VERSION 5.7 ;
  NOWIREEXTENSIONATPIN ON ;
  DIVIDERCHAR "/" ;
  BUSBITCHARS "[]" ;
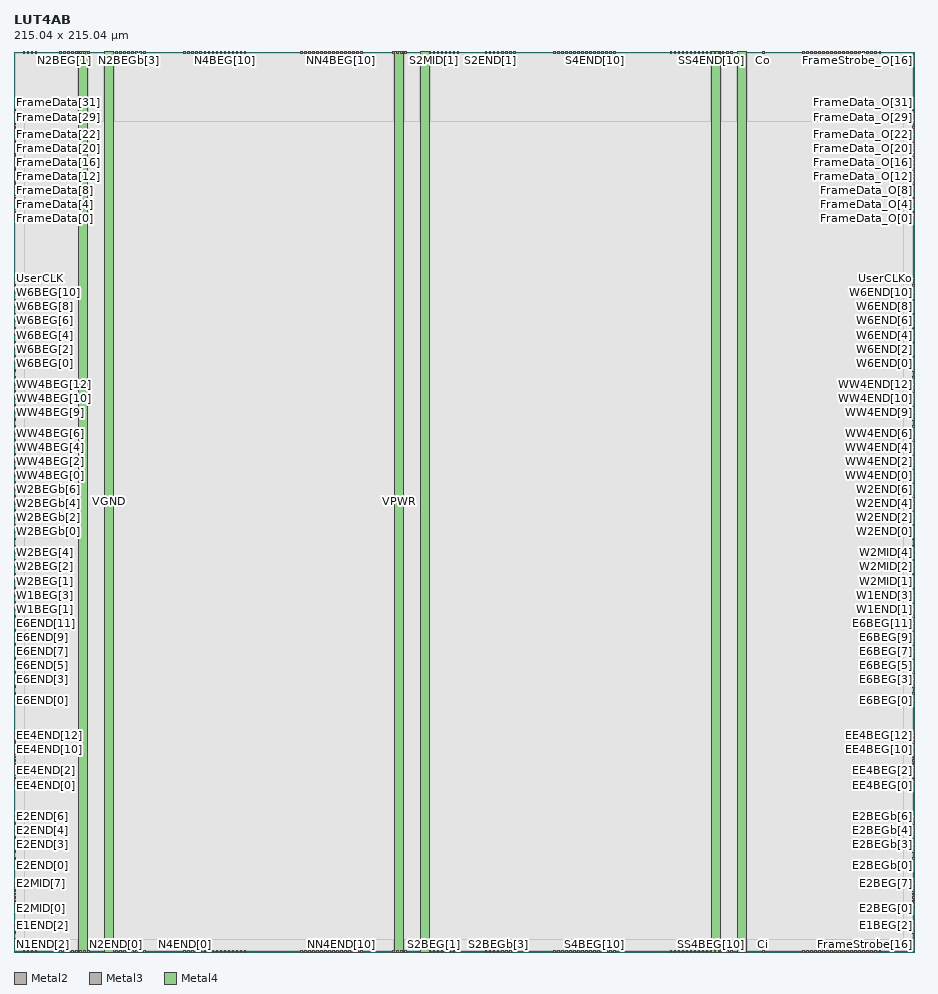
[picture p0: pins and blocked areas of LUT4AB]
MACRO LUT4AB
  CLASS BLOCK ;
  FOREIGN LUT4AB ;
  ORIGIN 0.000 0.000 ;
  SIZE 215.040 BY 215.040 ;
  PIN Ci
    DIRECTION INPUT ;
    USE SIGNAL ;
    ANTENNAGATEAREA 0.587600 ;
    PORT
      LAYER Metal2 ;
        RECT 178.840 0.000 179.240 0.400 ;
    END
  END Ci
  PIN Co
    DIRECTION OUTPUT ;
    USE SIGNAL ;
    ANTENNADIFFAREA 2.692600 ;
    PORT
      LAYER Metal2 ;
        RECT 178.840 214.640 179.240 215.040 ;
    END
  END Co
  PIN E1BEG[0]
    DIRECTION OUTPUT ;
    USE SIGNAL ;
    ANTENNADIFFAREA 2.724000 ;
    PORT
      LAYER Metal3 ;
        RECT 214.640 1.060 215.040 1.460 ;
    END
  END E1BEG[0]
  PIN E1BEG[1]
    DIRECTION OUTPUT ;
    USE SIGNAL ;
    ANTENNADIFFAREA 2.724000 ;
    PORT
      LAYER Metal3 ;
        RECT 214.640 2.740 215.040 3.140 ;
    END
  END E1BEG[1]
  PIN E1BEG[2]
    DIRECTION OUTPUT ;
    USE SIGNAL ;
    ANTENNADIFFAREA 2.724000 ;
    PORT
      LAYER Metal3 ;
        RECT 214.640 4.420 215.040 4.820 ;
    END
  END E1BEG[2]
  PIN E1BEG[3]
    DIRECTION OUTPUT ;
    USE SIGNAL ;
    ANTENNADIFFAREA 2.724000 ;
    PORT
      LAYER Metal3 ;
        RECT 214.640 6.100 215.040 6.500 ;
    END
  END E1BEG[3]
  PIN E1END[0]
    DIRECTION INPUT ;
    USE SIGNAL ;
    ANTENNAGATEAREA 1.917500 ;
    PORT
      LAYER Metal3 ;
        RECT 0.000 1.060 0.400 1.460 ;
    END
  END E1END[0]
  PIN E1END[1]
    DIRECTION INPUT ;
    USE SIGNAL ;
    ANTENNAGATEAREA 1.847300 ;
    PORT
      LAYER Metal3 ;
        RECT 0.000 2.740 0.400 3.140 ;
    END
  END E1END[1]
  PIN E1END[2]
    DIRECTION INPUT ;
    USE SIGNAL ;
    ANTENNAGATEAREA 2.448700 ;
    PORT
      LAYER Metal3 ;
        RECT 0.000 4.420 0.400 4.820 ;
    END
  END E1END[2]
  PIN E1END[3]
    DIRECTION INPUT ;
    USE SIGNAL ;
    ANTENNAGATEAREA 2.433100 ;
    PORT
      LAYER Metal3 ;
        RECT 0.000 6.100 0.400 6.500 ;
    END
  END E1END[3]
  PIN E2BEG[0]
    DIRECTION OUTPUT ;
    USE SIGNAL ;
    ANTENNADIFFAREA 2.724000 ;
    PORT
      LAYER Metal3 ;
        RECT 214.640 10.300 215.040 10.700 ;
    END
  END E2BEG[0]
  PIN E2BEG[1]
    DIRECTION OUTPUT ;
    USE SIGNAL ;
    ANTENNADIFFAREA 2.724000 ;
    PORT
      LAYER Metal3 ;
        RECT 214.640 11.140 215.040 11.540 ;
    END
  END E2BEG[1]
  PIN E2BEG[2]
    DIRECTION OUTPUT ;
    USE SIGNAL ;
    ANTENNADIFFAREA 2.724000 ;
    PORT
      LAYER Metal3 ;
        RECT 214.640 11.980 215.040 12.380 ;
    END
  END E2BEG[2]
  PIN E2BEG[3]
    DIRECTION OUTPUT ;
    USE SIGNAL ;
    ANTENNADIFFAREA 2.724000 ;
    PORT
      LAYER Metal3 ;
        RECT 214.640 12.820 215.040 13.220 ;
    END
  END E2BEG[3]
  PIN E2BEG[4]
    DIRECTION OUTPUT ;
    USE SIGNAL ;
    ANTENNADIFFAREA 2.724000 ;
    PORT
      LAYER Metal3 ;
        RECT 214.640 13.660 215.040 14.060 ;
    END
  END E2BEG[4]
  PIN E2BEG[5]
    DIRECTION OUTPUT ;
    USE SIGNAL ;
    ANTENNADIFFAREA 2.724000 ;
    PORT
      LAYER Metal3 ;
        RECT 214.640 14.500 215.040 14.900 ;
    END
  END E2BEG[5]
  PIN E2BEG[6]
    DIRECTION OUTPUT ;
    USE SIGNAL ;
    ANTENNADIFFAREA 2.724000 ;
    PORT
      LAYER Metal3 ;
        RECT 214.640 15.340 215.040 15.740 ;
    END
  END E2BEG[6]
  PIN E2BEG[7]
    DIRECTION OUTPUT ;
    USE SIGNAL ;
    ANTENNADIFFAREA 2.724000 ;
    PORT
      LAYER Metal3 ;
        RECT 214.640 16.180 215.040 16.580 ;
    END
  END E2BEG[7]
  PIN E2BEGb[0]
    DIRECTION OUTPUT ;
    USE SIGNAL ;
    ANTENNADIFFAREA 2.724000 ;
    PORT
      LAYER Metal3 ;
        RECT 214.640 20.380 215.040 20.780 ;
    END
  END E2BEGb[0]
  PIN E2BEGb[1]
    DIRECTION OUTPUT ;
    USE SIGNAL ;
    ANTENNADIFFAREA 2.724000 ;
    PORT
      LAYER Metal3 ;
        RECT 214.640 22.060 215.040 22.460 ;
    END
  END E2BEGb[1]
  PIN E2BEGb[2]
    DIRECTION OUTPUT ;
    USE SIGNAL ;
    ANTENNADIFFAREA 2.724000 ;
    PORT
      LAYER Metal3 ;
        RECT 214.640 23.740 215.040 24.140 ;
    END
  END E2BEGb[2]
  PIN E2BEGb[3]
    DIRECTION OUTPUT ;
    USE SIGNAL ;
    ANTENNADIFFAREA 2.724000 ;
    PORT
      LAYER Metal3 ;
        RECT 214.640 25.420 215.040 25.820 ;
    END
  END E2BEGb[3]
  PIN E2BEGb[4]
    DIRECTION OUTPUT ;
    USE SIGNAL ;
    ANTENNADIFFAREA 2.724000 ;
    PORT
      LAYER Metal3 ;
        RECT 214.640 27.100 215.040 27.500 ;
    END
  END E2BEGb[4]
  PIN E2BEGb[5]
    DIRECTION OUTPUT ;
    USE SIGNAL ;
    ANTENNADIFFAREA 2.724000 ;
    PORT
      LAYER Metal3 ;
        RECT 214.640 28.780 215.040 29.180 ;
    END
  END E2BEGb[5]
  PIN E2BEGb[6]
    DIRECTION OUTPUT ;
    USE SIGNAL ;
    ANTENNADIFFAREA 2.724000 ;
    PORT
      LAYER Metal3 ;
        RECT 214.640 30.460 215.040 30.860 ;
    END
  END E2BEGb[6]
  PIN E2BEGb[7]
    DIRECTION OUTPUT ;
    USE SIGNAL ;
    ANTENNADIFFAREA 2.724000 ;
    PORT
      LAYER Metal3 ;
        RECT 214.640 32.140 215.040 32.540 ;
    END
  END E2BEGb[7]
  PIN E2END[0]
    DIRECTION INPUT ;
    USE SIGNAL ;
    ANTENNAGATEAREA 0.944600 ;
    PORT
      LAYER Metal3 ;
        RECT 0.000 20.380 0.400 20.780 ;
    END
  END E2END[0]
  PIN E2END[1]
    DIRECTION INPUT ;
    USE SIGNAL ;
    ANTENNAGATEAREA 0.899100 ;
    PORT
      LAYER Metal3 ;
        RECT 0.000 22.060 0.400 22.460 ;
    END
  END E2END[1]
  PIN E2END[2]
    DIRECTION INPUT ;
    USE SIGNAL ;
    ANTENNAGATEAREA 1.498900 ;
    PORT
      LAYER Metal3 ;
        RECT 0.000 23.740 0.400 24.140 ;
    END
  END E2END[2]
  PIN E2END[3]
    DIRECTION INPUT ;
    USE SIGNAL ;
    ANTENNAGATEAREA 1.530100 ;
    PORT
      LAYER Metal3 ;
        RECT 0.000 25.420 0.400 25.820 ;
    END
  END E2END[3]
  PIN E2END[4]
    DIRECTION INPUT ;
    USE SIGNAL ;
    ANTENNAGATEAREA 1.059500 ;
    PORT
      LAYER Metal3 ;
        RECT 0.000 27.100 0.400 27.500 ;
    END
  END E2END[4]
  PIN E2END[5]
    DIRECTION INPUT ;
    USE SIGNAL ;
    ANTENNAGATEAREA 1.288300 ;
    PORT
      LAYER Metal3 ;
        RECT 0.000 28.780 0.400 29.180 ;
    END
  END E2END[5]
  PIN E2END[6]
    DIRECTION INPUT ;
    USE SIGNAL ;
    ANTENNAGATEAREA 1.439400 ;
    PORT
      LAYER Metal3 ;
        RECT 0.000 30.460 0.400 30.860 ;
    END
  END E2END[6]
  PIN E2END[7]
    DIRECTION INPUT ;
    USE SIGNAL ;
    ANTENNAGATEAREA 1.041300 ;
    PORT
      LAYER Metal3 ;
        RECT 0.000 32.140 0.400 32.540 ;
    END
  END E2END[7]
  PIN E2MID[0]
    DIRECTION INPUT ;
    USE SIGNAL ;
    ANTENNAGATEAREA 0.820300 ;
    PORT
      LAYER Metal3 ;
        RECT 0.000 10.300 0.400 10.700 ;
    END
  END E2MID[0]
  PIN E2MID[1]
    DIRECTION INPUT ;
    USE SIGNAL ;
    ANTENNAGATEAREA 1.033500 ;
    PORT
      LAYER Metal3 ;
        RECT 0.000 11.140 0.400 11.540 ;
    END
  END E2MID[1]
  PIN E2MID[2]
    DIRECTION INPUT ;
    USE SIGNAL ;
    ANTENNAGATEAREA 0.848900 ;
    PORT
      LAYER Metal3 ;
        RECT 0.000 11.980 0.400 12.380 ;
    END
  END E2MID[2]
  PIN E2MID[3]
    DIRECTION INPUT ;
    USE SIGNAL ;
    ANTENNAGATEAREA 1.033500 ;
    PORT
      LAYER Metal3 ;
        RECT 0.000 12.820 0.400 13.220 ;
    END
  END E2MID[3]
  PIN E2MID[4]
    DIRECTION INPUT ;
    USE SIGNAL ;
    ANTENNAGATEAREA 0.820300 ;
    PORT
      LAYER Metal3 ;
        RECT 0.000 13.660 0.400 14.060 ;
    END
  END E2MID[4]
  PIN E2MID[5]
    DIRECTION INPUT ;
    USE SIGNAL ;
    ANTENNAGATEAREA 1.033500 ;
    ANTENNADIFFAREA 10.077000 ;
    PORT
      LAYER Metal3 ;
        RECT 0.000 14.500 0.400 14.900 ;
    END
  END E2MID[5]
  PIN E2MID[6]
    DIRECTION INPUT ;
    USE SIGNAL ;
    ANTENNAGATEAREA 0.820300 ;
    ANTENNADIFFAREA 24.184799 ;
    PORT
      LAYER Metal3 ;
        RECT 0.000 15.340 0.400 15.740 ;
    END
  END E2MID[6]
  PIN E2MID[7]
    DIRECTION INPUT ;
    USE SIGNAL ;
    ANTENNAGATEAREA 1.033500 ;
    PORT
      LAYER Metal3 ;
        RECT 0.000 16.180 0.400 16.580 ;
    END
  END E2MID[7]
  PIN E6BEG[0]
    DIRECTION OUTPUT ;
    USE SIGNAL ;
    ANTENNADIFFAREA 2.724000 ;
    PORT
      LAYER Metal3 ;
        RECT 214.640 59.860 215.040 60.260 ;
    END
  END E6BEG[0]
  PIN E6BEG[10]
    DIRECTION OUTPUT ;
    USE SIGNAL ;
    ANTENNADIFFAREA 2.724000 ;
    PORT
      LAYER Metal3 ;
        RECT 214.640 76.660 215.040 77.060 ;
    END
  END E6BEG[10]
  PIN E6BEG[11]
    DIRECTION OUTPUT ;
    USE SIGNAL ;
    ANTENNADIFFAREA 2.724000 ;
    PORT
      LAYER Metal3 ;
        RECT 214.640 78.340 215.040 78.740 ;
    END
  END E6BEG[11]
  PIN E6BEG[1]
    DIRECTION OUTPUT ;
    USE SIGNAL ;
    ANTENNADIFFAREA 2.724000 ;
    PORT
      LAYER Metal3 ;
        RECT 214.640 61.540 215.040 61.940 ;
    END
  END E6BEG[1]
  PIN E6BEG[2]
    DIRECTION OUTPUT ;
    USE SIGNAL ;
    ANTENNADIFFAREA 2.724000 ;
    PORT
      LAYER Metal3 ;
        RECT 214.640 63.220 215.040 63.620 ;
    END
  END E6BEG[2]
  PIN E6BEG[3]
    DIRECTION OUTPUT ;
    USE SIGNAL ;
    ANTENNADIFFAREA 2.724000 ;
    PORT
      LAYER Metal3 ;
        RECT 214.640 64.900 215.040 65.300 ;
    END
  END E6BEG[3]
  PIN E6BEG[4]
    DIRECTION OUTPUT ;
    USE SIGNAL ;
    ANTENNADIFFAREA 2.724000 ;
    PORT
      LAYER Metal3 ;
        RECT 214.640 66.580 215.040 66.980 ;
    END
  END E6BEG[4]
  PIN E6BEG[5]
    DIRECTION OUTPUT ;
    USE SIGNAL ;
    ANTENNADIFFAREA 2.724000 ;
    PORT
      LAYER Metal3 ;
        RECT 214.640 68.260 215.040 68.660 ;
    END
  END E6BEG[5]
  PIN E6BEG[6]
    DIRECTION OUTPUT ;
    USE SIGNAL ;
    ANTENNADIFFAREA 2.724000 ;
    PORT
      LAYER Metal3 ;
        RECT 214.640 69.940 215.040 70.340 ;
    END
  END E6BEG[6]
  PIN E6BEG[7]
    DIRECTION OUTPUT ;
    USE SIGNAL ;
    ANTENNADIFFAREA 2.724000 ;
    PORT
      LAYER Metal3 ;
        RECT 214.640 71.620 215.040 72.020 ;
    END
  END E6BEG[7]
  PIN E6BEG[8]
    DIRECTION OUTPUT ;
    USE SIGNAL ;
    ANTENNADIFFAREA 2.724000 ;
    PORT
      LAYER Metal3 ;
        RECT 214.640 73.300 215.040 73.700 ;
    END
  END E6BEG[8]
  PIN E6BEG[9]
    DIRECTION OUTPUT ;
    USE SIGNAL ;
    ANTENNADIFFAREA 2.724000 ;
    PORT
      LAYER Metal3 ;
        RECT 214.640 74.980 215.040 75.380 ;
    END
  END E6BEG[9]
  PIN E6END[0]
    DIRECTION INPUT ;
    USE SIGNAL ;
    ANTENNAGATEAREA 2.678800 ;
    PORT
      LAYER Metal3 ;
        RECT 0.000 59.860 0.400 60.260 ;
    END
  END E6END[0]
  PIN E6END[10]
    DIRECTION INPUT ;
    USE SIGNAL ;
    ANTENNAGATEAREA 0.180700 ;
    PORT
      LAYER Metal3 ;
        RECT 0.000 76.660 0.400 77.060 ;
    END
  END E6END[10]
  PIN E6END[11]
    DIRECTION INPUT ;
    USE SIGNAL ;
    ANTENNAGATEAREA 0.180700 ;
    PORT
      LAYER Metal3 ;
        RECT 0.000 78.340 0.400 78.740 ;
    END
  END E6END[11]
  PIN E6END[1]
    DIRECTION INPUT ;
    USE SIGNAL ;
    ANTENNAGATEAREA 2.637700 ;
    PORT
      LAYER Metal3 ;
        RECT 0.000 61.540 0.400 61.940 ;
    END
  END E6END[1]
  PIN E6END[2]
    DIRECTION INPUT ;
    USE SIGNAL ;
    ANTENNAGATEAREA 0.180700 ;
    PORT
      LAYER Metal3 ;
        RECT 0.000 63.220 0.400 63.620 ;
    END
  END E6END[2]
  PIN E6END[3]
    DIRECTION INPUT ;
    USE SIGNAL ;
    ANTENNAGATEAREA 0.180700 ;
    PORT
      LAYER Metal3 ;
        RECT 0.000 64.900 0.400 65.300 ;
    END
  END E6END[3]
  PIN E6END[4]
    DIRECTION INPUT ;
    USE SIGNAL ;
    ANTENNAGATEAREA 0.180700 ;
    PORT
      LAYER Metal3 ;
        RECT 0.000 66.580 0.400 66.980 ;
    END
  END E6END[4]
  PIN E6END[5]
    DIRECTION INPUT ;
    USE SIGNAL ;
    ANTENNAGATEAREA 0.180700 ;
    PORT
      LAYER Metal3 ;
        RECT 0.000 68.260 0.400 68.660 ;
    END
  END E6END[5]
  PIN E6END[6]
    DIRECTION INPUT ;
    USE SIGNAL ;
    ANTENNAGATEAREA 0.180700 ;
    PORT
      LAYER Metal3 ;
        RECT 0.000 69.940 0.400 70.340 ;
    END
  END E6END[6]
  PIN E6END[7]
    DIRECTION INPUT ;
    USE SIGNAL ;
    ANTENNAGATEAREA 0.180700 ;
    PORT
      LAYER Metal3 ;
        RECT 0.000 71.620 0.400 72.020 ;
    END
  END E6END[7]
  PIN E6END[8]
    DIRECTION INPUT ;
    USE SIGNAL ;
    ANTENNAGATEAREA 0.180700 ;
    PORT
      LAYER Metal3 ;
        RECT 0.000 73.300 0.400 73.700 ;
    END
  END E6END[8]
  PIN E6END[9]
    DIRECTION INPUT ;
    USE SIGNAL ;
    ANTENNAGATEAREA 0.180700 ;
    PORT
      LAYER Metal3 ;
        RECT 0.000 74.980 0.400 75.380 ;
    END
  END E6END[9]
  PIN EE4BEG[0]
    DIRECTION OUTPUT ;
    USE SIGNAL ;
    ANTENNADIFFAREA 2.724000 ;
    PORT
      LAYER Metal3 ;
        RECT 214.640 39.700 215.040 40.100 ;
    END
  END EE4BEG[0]
  PIN EE4BEG[10]
    DIRECTION OUTPUT ;
    USE SIGNAL ;
    ANTENNADIFFAREA 2.724000 ;
    PORT
      LAYER Metal3 ;
        RECT 214.640 48.100 215.040 48.500 ;
    END
  END EE4BEG[10]
  PIN EE4BEG[11]
    DIRECTION OUTPUT ;
    USE SIGNAL ;
    ANTENNADIFFAREA 2.724000 ;
    PORT
      LAYER Metal3 ;
        RECT 214.640 48.940 215.040 49.340 ;
    END
  END EE4BEG[11]
  PIN EE4BEG[12]
    DIRECTION OUTPUT ;
    USE SIGNAL ;
    ANTENNADIFFAREA 2.724000 ;
    PORT
      LAYER Metal3 ;
        RECT 214.640 49.780 215.040 50.180 ;
    END
  END EE4BEG[12]
  PIN EE4BEG[13]
    DIRECTION OUTPUT ;
    USE SIGNAL ;
    ANTENNADIFFAREA 2.724000 ;
    PORT
      LAYER Metal3 ;
        RECT 214.640 50.620 215.040 51.020 ;
    END
  END EE4BEG[13]
  PIN EE4BEG[14]
    DIRECTION OUTPUT ;
    USE SIGNAL ;
    ANTENNADIFFAREA 2.724000 ;
    PORT
      LAYER Metal3 ;
        RECT 214.640 51.460 215.040 51.860 ;
    END
  END EE4BEG[14]
  PIN EE4BEG[15]
    DIRECTION OUTPUT ;
    USE SIGNAL ;
    ANTENNADIFFAREA 2.724000 ;
    PORT
      LAYER Metal3 ;
        RECT 214.640 52.300 215.040 52.700 ;
    END
  END EE4BEG[15]
  PIN EE4BEG[1]
    DIRECTION OUTPUT ;
    USE SIGNAL ;
    ANTENNADIFFAREA 2.724000 ;
    PORT
      LAYER Metal3 ;
        RECT 214.640 40.540 215.040 40.940 ;
    END
  END EE4BEG[1]
  PIN EE4BEG[2]
    DIRECTION OUTPUT ;
    USE SIGNAL ;
    ANTENNADIFFAREA 2.724000 ;
    PORT
      LAYER Metal3 ;
        RECT 214.640 41.380 215.040 41.780 ;
    END
  END EE4BEG[2]
  PIN EE4BEG[3]
    DIRECTION OUTPUT ;
    USE SIGNAL ;
    ANTENNADIFFAREA 2.724000 ;
    PORT
      LAYER Metal3 ;
        RECT 214.640 42.220 215.040 42.620 ;
    END
  END EE4BEG[3]
  PIN EE4BEG[4]
    DIRECTION OUTPUT ;
    USE SIGNAL ;
    ANTENNADIFFAREA 2.724000 ;
    PORT
      LAYER Metal3 ;
        RECT 214.640 43.060 215.040 43.460 ;
    END
  END EE4BEG[4]
  PIN EE4BEG[5]
    DIRECTION OUTPUT ;
    USE SIGNAL ;
    ANTENNADIFFAREA 2.724000 ;
    PORT
      LAYER Metal3 ;
        RECT 214.640 43.900 215.040 44.300 ;
    END
  END EE4BEG[5]
  PIN EE4BEG[6]
    DIRECTION OUTPUT ;
    USE SIGNAL ;
    ANTENNADIFFAREA 2.724000 ;
    PORT
      LAYER Metal3 ;
        RECT 214.640 44.740 215.040 45.140 ;
    END
  END EE4BEG[6]
  PIN EE4BEG[7]
    DIRECTION OUTPUT ;
    USE SIGNAL ;
    ANTENNADIFFAREA 2.724000 ;
    PORT
      LAYER Metal3 ;
        RECT 214.640 45.580 215.040 45.980 ;
    END
  END EE4BEG[7]
  PIN EE4BEG[8]
    DIRECTION OUTPUT ;
    USE SIGNAL ;
    ANTENNADIFFAREA 2.724000 ;
    PORT
      LAYER Metal3 ;
        RECT 214.640 46.420 215.040 46.820 ;
    END
  END EE4BEG[8]
  PIN EE4BEG[9]
    DIRECTION OUTPUT ;
    USE SIGNAL ;
    ANTENNADIFFAREA 2.724000 ;
    PORT
      LAYER Metal3 ;
        RECT 214.640 47.260 215.040 47.660 ;
    END
  END EE4BEG[9]
  PIN EE4END[0]
    DIRECTION INPUT ;
    USE SIGNAL ;
    ANTENNAGATEAREA 0.607100 ;
    ANTENNADIFFAREA 12.092400 ;
    PORT
      LAYER Metal3 ;
        RECT 0.000 39.700 0.400 40.100 ;
    END
  END EE4END[0]
  PIN EE4END[10]
    DIRECTION INPUT ;
    USE SIGNAL ;
    ANTENNAGATEAREA 0.180700 ;
    PORT
      LAYER Metal3 ;
        RECT 0.000 48.100 0.400 48.500 ;
    END
  END EE4END[10]
  PIN EE4END[11]
    DIRECTION INPUT ;
    USE SIGNAL ;
    ANTENNAGATEAREA 0.180700 ;
    PORT
      LAYER Metal3 ;
        RECT 0.000 48.940 0.400 49.340 ;
    END
  END EE4END[11]
  PIN EE4END[12]
    DIRECTION INPUT ;
    USE SIGNAL ;
    ANTENNAGATEAREA 0.180700 ;
    PORT
      LAYER Metal3 ;
        RECT 0.000 49.780 0.400 50.180 ;
    END
  END EE4END[12]
  PIN EE4END[13]
    DIRECTION INPUT ;
    USE SIGNAL ;
    ANTENNAGATEAREA 0.180700 ;
    PORT
      LAYER Metal3 ;
        RECT 0.000 50.620 0.400 51.020 ;
    END
  END EE4END[13]
  PIN EE4END[14]
    DIRECTION INPUT ;
    USE SIGNAL ;
    ANTENNAGATEAREA 0.180700 ;
    PORT
      LAYER Metal3 ;
        RECT 0.000 51.460 0.400 51.860 ;
    END
  END EE4END[14]
  PIN EE4END[15]
    DIRECTION INPUT ;
    USE SIGNAL ;
    ANTENNAGATEAREA 0.180700 ;
    PORT
      LAYER Metal3 ;
        RECT 0.000 52.300 0.400 52.700 ;
    END
  END EE4END[15]
  PIN EE4END[1]
    DIRECTION INPUT ;
    USE SIGNAL ;
    ANTENNAGATEAREA 0.620100 ;
    PORT
      LAYER Metal3 ;
        RECT 0.000 40.540 0.400 40.940 ;
    END
  END EE4END[1]
  PIN EE4END[2]
    DIRECTION INPUT ;
    USE SIGNAL ;
    ANTENNAGATEAREA 0.681200 ;
    ANTENNADIFFAREA 18.138599 ;
    PORT
      LAYER Metal3 ;
        RECT 0.000 41.380 0.400 41.780 ;
    END
  END EE4END[2]
  PIN EE4END[3]
    DIRECTION INPUT ;
    USE SIGNAL ;
    ANTENNAGATEAREA 0.678600 ;
    PORT
      LAYER Metal3 ;
        RECT 0.000 42.220 0.400 42.620 ;
    END
  END EE4END[3]
  PIN EE4END[4]
    DIRECTION INPUT ;
    USE SIGNAL ;
    ANTENNAGATEAREA 0.180700 ;
    ANTENNADIFFAREA 2.015400 ;
    PORT
      LAYER Metal3 ;
        RECT 0.000 43.060 0.400 43.460 ;
    END
  END EE4END[4]
  PIN EE4END[5]
    DIRECTION INPUT ;
    USE SIGNAL ;
    ANTENNAGATEAREA 0.180700 ;
    PORT
      LAYER Metal3 ;
        RECT 0.000 43.900 0.400 44.300 ;
    END
  END EE4END[5]
  PIN EE4END[6]
    DIRECTION INPUT ;
    USE SIGNAL ;
    ANTENNAGATEAREA 0.180700 ;
    PORT
      LAYER Metal3 ;
        RECT 0.000 44.740 0.400 45.140 ;
    END
  END EE4END[6]
  PIN EE4END[7]
    DIRECTION INPUT ;
    USE SIGNAL ;
    ANTENNAGATEAREA 0.180700 ;
    PORT
      LAYER Metal3 ;
        RECT 0.000 45.580 0.400 45.980 ;
    END
  END EE4END[7]
  PIN EE4END[8]
    DIRECTION INPUT ;
    USE SIGNAL ;
    ANTENNAGATEAREA 0.180700 ;
    PORT
      LAYER Metal3 ;
        RECT 0.000 46.420 0.400 46.820 ;
    END
  END EE4END[8]
  PIN EE4END[9]
    DIRECTION INPUT ;
    USE SIGNAL ;
    ANTENNAGATEAREA 0.180700 ;
    PORT
      LAYER Metal3 ;
        RECT 0.000 47.260 0.400 47.660 ;
    END
  END EE4END[9]
  PIN FrameData[0]
    DIRECTION INPUT ;
    USE SIGNAL ;
    ANTENNAGATEAREA 3.071900 ;
    PORT
      LAYER Metal3 ;
        RECT 0.000 174.940 0.400 175.340 ;
    END
  END FrameData[0]
  PIN FrameData[10]
    DIRECTION INPUT ;
    USE SIGNAL ;
    ANTENNAGATEAREA 3.794700 ;
    PORT
      LAYER Metal3 ;
        RECT 0.000 183.340 0.400 183.740 ;
    END
  END FrameData[10]
  PIN FrameData[11]
    DIRECTION INPUT ;
    USE SIGNAL ;
    ANTENNAGATEAREA 3.794700 ;
    PORT
      LAYER Metal3 ;
        RECT 0.000 184.180 0.400 184.580 ;
    END
  END FrameData[11]
  PIN FrameData[12]
    DIRECTION INPUT ;
    USE SIGNAL ;
    ANTENNAGATEAREA 3.794700 ;
    PORT
      LAYER Metal3 ;
        RECT 0.000 185.020 0.400 185.420 ;
    END
  END FrameData[12]
  PIN FrameData[13]
    DIRECTION INPUT ;
    USE SIGNAL ;
    ANTENNAGATEAREA 3.794700 ;
    PORT
      LAYER Metal3 ;
        RECT 0.000 185.860 0.400 186.260 ;
    END
  END FrameData[13]
  PIN FrameData[14]
    DIRECTION INPUT ;
    USE SIGNAL ;
    ANTENNAGATEAREA 3.794700 ;
    PORT
      LAYER Metal3 ;
        RECT 0.000 186.700 0.400 187.100 ;
    END
  END FrameData[14]
  PIN FrameData[15]
    DIRECTION INPUT ;
    USE SIGNAL ;
    ANTENNAGATEAREA 3.794700 ;
    PORT
      LAYER Metal3 ;
        RECT 0.000 187.540 0.400 187.940 ;
    END
  END FrameData[15]
  PIN FrameData[16]
    DIRECTION INPUT ;
    USE SIGNAL ;
    ANTENNAGATEAREA 3.794700 ;
    PORT
      LAYER Metal3 ;
        RECT 0.000 188.380 0.400 188.780 ;
    END
  END FrameData[16]
  PIN FrameData[17]
    DIRECTION INPUT ;
    USE SIGNAL ;
    ANTENNAGATEAREA 3.794700 ;
    PORT
      LAYER Metal3 ;
        RECT 0.000 189.220 0.400 189.620 ;
    END
  END FrameData[17]
  PIN FrameData[18]
    DIRECTION INPUT ;
    USE SIGNAL ;
    ANTENNAGATEAREA 3.794700 ;
    PORT
      LAYER Metal3 ;
        RECT 0.000 190.060 0.400 190.460 ;
    END
  END FrameData[18]
  PIN FrameData[19]
    DIRECTION INPUT ;
    USE SIGNAL ;
    ANTENNAGATEAREA 3.794700 ;
    PORT
      LAYER Metal3 ;
        RECT 0.000 190.900 0.400 191.300 ;
    END
  END FrameData[19]
  PIN FrameData[1]
    DIRECTION INPUT ;
    USE SIGNAL ;
    ANTENNAGATEAREA 3.433300 ;
    PORT
      LAYER Metal3 ;
        RECT 0.000 175.780 0.400 176.180 ;
    END
  END FrameData[1]
  PIN FrameData[20]
    DIRECTION INPUT ;
    USE SIGNAL ;
    ANTENNAGATEAREA 3.794700 ;
    PORT
      LAYER Metal3 ;
        RECT 0.000 191.740 0.400 192.140 ;
    END
  END FrameData[20]
  PIN FrameData[21]
    DIRECTION INPUT ;
    USE SIGNAL ;
    ANTENNAGATEAREA 3.794700 ;
    PORT
      LAYER Metal3 ;
        RECT 0.000 192.580 0.400 192.980 ;
    END
  END FrameData[21]
  PIN FrameData[22]
    DIRECTION INPUT ;
    USE SIGNAL ;
    ANTENNAGATEAREA 3.794700 ;
    PORT
      LAYER Metal3 ;
        RECT 0.000 193.420 0.400 193.820 ;
    END
  END FrameData[22]
  PIN FrameData[23]
    DIRECTION INPUT ;
    USE SIGNAL ;
    ANTENNAGATEAREA 3.794700 ;
    PORT
      LAYER Metal3 ;
        RECT 0.000 194.260 0.400 194.660 ;
    END
  END FrameData[23]
  PIN FrameData[24]
    DIRECTION INPUT ;
    USE SIGNAL ;
    ANTENNAGATEAREA 3.794700 ;
    PORT
      LAYER Metal3 ;
        RECT 0.000 195.100 0.400 195.500 ;
    END
  END FrameData[24]
  PIN FrameData[25]
    DIRECTION INPUT ;
    USE SIGNAL ;
    ANTENNAGATEAREA 3.614000 ;
    PORT
      LAYER Metal3 ;
        RECT 0.000 195.940 0.400 196.340 ;
    END
  END FrameData[25]
  PIN FrameData[26]
    DIRECTION INPUT ;
    USE SIGNAL ;
    ANTENNAGATEAREA 3.433300 ;
    PORT
      LAYER Metal3 ;
        RECT 0.000 196.780 0.400 197.180 ;
    END
  END FrameData[26]
  PIN FrameData[27]
    DIRECTION INPUT ;
    USE SIGNAL ;
    ANTENNAGATEAREA 3.433300 ;
    PORT
      LAYER Metal3 ;
        RECT 0.000 197.620 0.400 198.020 ;
    END
  END FrameData[27]
  PIN FrameData[28]
    DIRECTION INPUT ;
    USE SIGNAL ;
    ANTENNAGATEAREA 3.433300 ;
    PORT
      LAYER Metal3 ;
        RECT 0.000 198.460 0.400 198.860 ;
    END
  END FrameData[28]
  PIN FrameData[29]
    DIRECTION INPUT ;
    USE SIGNAL ;
    ANTENNAGATEAREA 3.252600 ;
    PORT
      LAYER Metal3 ;
        RECT 0.000 199.300 0.400 199.700 ;
    END
  END FrameData[29]
  PIN FrameData[2]
    DIRECTION INPUT ;
    USE SIGNAL ;
    ANTENNAGATEAREA 3.433300 ;
    PORT
      LAYER Metal3 ;
        RECT 0.000 176.620 0.400 177.020 ;
    END
  END FrameData[2]
  PIN FrameData[30]
    DIRECTION INPUT ;
    USE SIGNAL ;
    ANTENNAGATEAREA 3.433300 ;
    PORT
      LAYER Metal3 ;
        RECT 0.000 200.140 0.400 200.540 ;
    END
  END FrameData[30]
  PIN FrameData[31]
    DIRECTION INPUT ;
    USE SIGNAL ;
    ANTENNAGATEAREA 3.433300 ;
    PORT
      LAYER Metal3 ;
        RECT 0.000 200.980 0.400 201.380 ;
    END
  END FrameData[31]
  PIN FrameData[3]
    DIRECTION INPUT ;
    USE SIGNAL ;
    ANTENNAGATEAREA 3.614000 ;
    PORT
      LAYER Metal3 ;
        RECT 0.000 177.460 0.400 177.860 ;
    END
  END FrameData[3]
  PIN FrameData[4]
    DIRECTION INPUT ;
    USE SIGNAL ;
    ANTENNAGATEAREA 3.794700 ;
    PORT
      LAYER Metal3 ;
        RECT 0.000 178.300 0.400 178.700 ;
    END
  END FrameData[4]
  PIN FrameData[5]
    DIRECTION INPUT ;
    USE SIGNAL ;
    ANTENNAGATEAREA 3.794700 ;
    PORT
      LAYER Metal3 ;
        RECT 0.000 179.140 0.400 179.540 ;
    END
  END FrameData[5]
  PIN FrameData[6]
    DIRECTION INPUT ;
    USE SIGNAL ;
    ANTENNAGATEAREA 3.614000 ;
    PORT
      LAYER Metal3 ;
        RECT 0.000 179.980 0.400 180.380 ;
    END
  END FrameData[6]
  PIN FrameData[7]
    DIRECTION INPUT ;
    USE SIGNAL ;
    ANTENNAGATEAREA 3.794700 ;
    PORT
      LAYER Metal3 ;
        RECT 0.000 180.820 0.400 181.220 ;
    END
  END FrameData[7]
  PIN FrameData[8]
    DIRECTION INPUT ;
    USE SIGNAL ;
    ANTENNAGATEAREA 3.794700 ;
    PORT
      LAYER Metal3 ;
        RECT 0.000 181.660 0.400 182.060 ;
    END
  END FrameData[8]
  PIN FrameData[9]
    DIRECTION INPUT ;
    USE SIGNAL ;
    ANTENNAGATEAREA 3.794700 ;
    PORT
      LAYER Metal3 ;
        RECT 0.000 182.500 0.400 182.900 ;
    END
  END FrameData[9]
  PIN FrameData_O[0]
    DIRECTION OUTPUT ;
    USE SIGNAL ;
    ANTENNADIFFAREA 2.724000 ;
    PORT
      LAYER Metal3 ;
        RECT 214.640 174.940 215.040 175.340 ;
    END
  END FrameData_O[0]
  PIN FrameData_O[10]
    DIRECTION OUTPUT ;
    USE SIGNAL ;
    ANTENNADIFFAREA 2.724000 ;
    PORT
      LAYER Metal3 ;
        RECT 214.640 183.340 215.040 183.740 ;
    END
  END FrameData_O[10]
  PIN FrameData_O[11]
    DIRECTION OUTPUT ;
    USE SIGNAL ;
    ANTENNADIFFAREA 2.724000 ;
    PORT
      LAYER Metal3 ;
        RECT 214.640 184.180 215.040 184.580 ;
    END
  END FrameData_O[11]
  PIN FrameData_O[12]
    DIRECTION OUTPUT ;
    USE SIGNAL ;
    ANTENNADIFFAREA 2.724000 ;
    PORT
      LAYER Metal3 ;
        RECT 214.640 185.020 215.040 185.420 ;
    END
  END FrameData_O[12]
  PIN FrameData_O[13]
    DIRECTION OUTPUT ;
    USE SIGNAL ;
    ANTENNADIFFAREA 2.724000 ;
    PORT
      LAYER Metal3 ;
        RECT 214.640 185.860 215.040 186.260 ;
    END
  END FrameData_O[13]
  PIN FrameData_O[14]
    DIRECTION OUTPUT ;
    USE SIGNAL ;
    ANTENNADIFFAREA 2.724000 ;
    PORT
      LAYER Metal3 ;
        RECT 214.640 186.700 215.040 187.100 ;
    END
  END FrameData_O[14]
  PIN FrameData_O[15]
    DIRECTION OUTPUT ;
    USE SIGNAL ;
    ANTENNADIFFAREA 2.724000 ;
    PORT
      LAYER Metal3 ;
        RECT 214.640 187.540 215.040 187.940 ;
    END
  END FrameData_O[15]
  PIN FrameData_O[16]
    DIRECTION OUTPUT ;
    USE SIGNAL ;
    ANTENNADIFFAREA 2.724000 ;
    PORT
      LAYER Metal3 ;
        RECT 214.640 188.380 215.040 188.780 ;
    END
  END FrameData_O[16]
  PIN FrameData_O[17]
    DIRECTION OUTPUT ;
    USE SIGNAL ;
    ANTENNADIFFAREA 2.724000 ;
    PORT
      LAYER Metal3 ;
        RECT 214.640 189.220 215.040 189.620 ;
    END
  END FrameData_O[17]
  PIN FrameData_O[18]
    DIRECTION OUTPUT ;
    USE SIGNAL ;
    ANTENNADIFFAREA 2.724000 ;
    PORT
      LAYER Metal3 ;
        RECT 214.640 190.060 215.040 190.460 ;
    END
  END FrameData_O[18]
  PIN FrameData_O[19]
    DIRECTION OUTPUT ;
    USE SIGNAL ;
    ANTENNADIFFAREA 2.724000 ;
    PORT
      LAYER Metal3 ;
        RECT 214.640 190.900 215.040 191.300 ;
    END
  END FrameData_O[19]
  PIN FrameData_O[1]
    DIRECTION OUTPUT ;
    USE SIGNAL ;
    ANTENNADIFFAREA 2.724000 ;
    PORT
      LAYER Metal3 ;
        RECT 214.640 175.780 215.040 176.180 ;
    END
  END FrameData_O[1]
  PIN FrameData_O[20]
    DIRECTION OUTPUT ;
    USE SIGNAL ;
    ANTENNADIFFAREA 2.724000 ;
    PORT
      LAYER Metal3 ;
        RECT 214.640 191.740 215.040 192.140 ;
    END
  END FrameData_O[20]
  PIN FrameData_O[21]
    DIRECTION OUTPUT ;
    USE SIGNAL ;
    ANTENNADIFFAREA 2.724000 ;
    PORT
      LAYER Metal3 ;
        RECT 214.640 192.580 215.040 192.980 ;
    END
  END FrameData_O[21]
  PIN FrameData_O[22]
    DIRECTION OUTPUT ;
    USE SIGNAL ;
    ANTENNADIFFAREA 2.724000 ;
    PORT
      LAYER Metal3 ;
        RECT 214.640 193.420 215.040 193.820 ;
    END
  END FrameData_O[22]
  PIN FrameData_O[23]
    DIRECTION OUTPUT ;
    USE SIGNAL ;
    ANTENNADIFFAREA 2.724000 ;
    PORT
      LAYER Metal3 ;
        RECT 214.640 194.260 215.040 194.660 ;
    END
  END FrameData_O[23]
  PIN FrameData_O[24]
    DIRECTION OUTPUT ;
    USE SIGNAL ;
    ANTENNADIFFAREA 2.724000 ;
    PORT
      LAYER Metal3 ;
        RECT 214.640 195.100 215.040 195.500 ;
    END
  END FrameData_O[24]
  PIN FrameData_O[25]
    DIRECTION OUTPUT ;
    USE SIGNAL ;
    ANTENNADIFFAREA 2.724000 ;
    PORT
      LAYER Metal3 ;
        RECT 214.640 195.940 215.040 196.340 ;
    END
  END FrameData_O[25]
  PIN FrameData_O[26]
    DIRECTION OUTPUT ;
    USE SIGNAL ;
    ANTENNADIFFAREA 2.724000 ;
    PORT
      LAYER Metal3 ;
        RECT 214.640 196.780 215.040 197.180 ;
    END
  END FrameData_O[26]
  PIN FrameData_O[27]
    DIRECTION OUTPUT ;
    USE SIGNAL ;
    ANTENNADIFFAREA 2.724000 ;
    PORT
      LAYER Metal3 ;
        RECT 214.640 197.620 215.040 198.020 ;
    END
  END FrameData_O[27]
  PIN FrameData_O[28]
    DIRECTION OUTPUT ;
    USE SIGNAL ;
    ANTENNADIFFAREA 2.724000 ;
    PORT
      LAYER Metal3 ;
        RECT 214.640 198.460 215.040 198.860 ;
    END
  END FrameData_O[28]
  PIN FrameData_O[29]
    DIRECTION OUTPUT ;
    USE SIGNAL ;
    ANTENNADIFFAREA 2.724000 ;
    PORT
      LAYER Metal3 ;
        RECT 214.640 199.300 215.040 199.700 ;
    END
  END FrameData_O[29]
  PIN FrameData_O[2]
    DIRECTION OUTPUT ;
    USE SIGNAL ;
    ANTENNADIFFAREA 2.724000 ;
    PORT
      LAYER Metal3 ;
        RECT 214.640 176.620 215.040 177.020 ;
    END
  END FrameData_O[2]
  PIN FrameData_O[30]
    DIRECTION OUTPUT ;
    USE SIGNAL ;
    ANTENNADIFFAREA 2.724000 ;
    PORT
      LAYER Metal3 ;
        RECT 214.640 200.140 215.040 200.540 ;
    END
  END FrameData_O[30]
  PIN FrameData_O[31]
    DIRECTION OUTPUT ;
    USE SIGNAL ;
    ANTENNADIFFAREA 2.724000 ;
    PORT
      LAYER Metal3 ;
        RECT 214.640 200.980 215.040 201.380 ;
    END
  END FrameData_O[31]
  PIN FrameData_O[3]
    DIRECTION OUTPUT ;
    USE SIGNAL ;
    ANTENNADIFFAREA 2.724000 ;
    PORT
      LAYER Metal3 ;
        RECT 214.640 177.460 215.040 177.860 ;
    END
  END FrameData_O[3]
  PIN FrameData_O[4]
    DIRECTION OUTPUT ;
    USE SIGNAL ;
    ANTENNADIFFAREA 2.724000 ;
    PORT
      LAYER Metal3 ;
        RECT 214.640 178.300 215.040 178.700 ;
    END
  END FrameData_O[4]
  PIN FrameData_O[5]
    DIRECTION OUTPUT ;
    USE SIGNAL ;
    ANTENNADIFFAREA 2.724000 ;
    PORT
      LAYER Metal3 ;
        RECT 214.640 179.140 215.040 179.540 ;
    END
  END FrameData_O[5]
  PIN FrameData_O[6]
    DIRECTION OUTPUT ;
    USE SIGNAL ;
    ANTENNADIFFAREA 2.724000 ;
    PORT
      LAYER Metal3 ;
        RECT 214.640 179.980 215.040 180.380 ;
    END
  END FrameData_O[6]
  PIN FrameData_O[7]
    DIRECTION OUTPUT ;
    USE SIGNAL ;
    ANTENNADIFFAREA 2.724000 ;
    PORT
      LAYER Metal3 ;
        RECT 214.640 180.820 215.040 181.220 ;
    END
  END FrameData_O[7]
  PIN FrameData_O[8]
    DIRECTION OUTPUT ;
    USE SIGNAL ;
    ANTENNADIFFAREA 2.724000 ;
    PORT
      LAYER Metal3 ;
        RECT 214.640 181.660 215.040 182.060 ;
    END
  END FrameData_O[8]
  PIN FrameData_O[9]
    DIRECTION OUTPUT ;
    USE SIGNAL ;
    ANTENNADIFFAREA 2.724000 ;
    PORT
      LAYER Metal3 ;
        RECT 214.640 182.500 215.040 182.900 ;
    END
  END FrameData_O[9]
  PIN FrameStrobe[0]
    DIRECTION INPUT ;
    USE SIGNAL ;
    ANTENNAGATEAREA 5.110300 ;
    PORT
      LAYER Metal2 ;
        RECT 188.440 0.000 188.840 0.400 ;
    END
  END FrameStrobe[0]
  PIN FrameStrobe[10]
    DIRECTION INPUT ;
    USE SIGNAL ;
    ANTENNAGATEAREA 6.753500 ;
    PORT
      LAYER Metal2 ;
        RECT 198.040 0.000 198.440 0.400 ;
    END
  END FrameStrobe[10]
  PIN FrameStrobe[11]
    DIRECTION INPUT ;
    USE SIGNAL ;
    ANTENNAGATEAREA 6.753500 ;
    PORT
      LAYER Metal2 ;
        RECT 199.000 0.000 199.400 0.400 ;
    END
  END FrameStrobe[11]
  PIN FrameStrobe[12]
    DIRECTION INPUT ;
    USE SIGNAL ;
    ANTENNAGATEAREA 6.753500 ;
    PORT
      LAYER Metal2 ;
        RECT 199.960 0.000 200.360 0.400 ;
    END
  END FrameStrobe[12]
  PIN FrameStrobe[13]
    DIRECTION INPUT ;
    USE SIGNAL ;
    ANTENNAGATEAREA 6.753500 ;
    PORT
      LAYER Metal2 ;
        RECT 200.920 0.000 201.320 0.400 ;
    END
  END FrameStrobe[13]
  PIN FrameStrobe[14]
    DIRECTION INPUT ;
    USE SIGNAL ;
    ANTENNAGATEAREA 6.753500 ;
    PORT
      LAYER Metal2 ;
        RECT 201.880 0.000 202.280 0.400 ;
    END
  END FrameStrobe[14]
  PIN FrameStrobe[15]
    DIRECTION INPUT ;
    USE SIGNAL ;
    ANTENNAGATEAREA 6.753500 ;
    PORT
      LAYER Metal2 ;
        RECT 202.840 0.000 203.240 0.400 ;
    END
  END FrameStrobe[15]
  PIN FrameStrobe[16]
    DIRECTION INPUT ;
    USE SIGNAL ;
    ANTENNAGATEAREA 6.753500 ;
    PORT
      LAYER Metal2 ;
        RECT 203.800 0.000 204.200 0.400 ;
    END
  END FrameStrobe[16]
  PIN FrameStrobe[17]
    DIRECTION INPUT ;
    USE SIGNAL ;
    ANTENNAGATEAREA 6.753500 ;
    PORT
      LAYER Metal2 ;
        RECT 204.760 0.000 205.160 0.400 ;
    END
  END FrameStrobe[17]
  PIN FrameStrobe[18]
    DIRECTION INPUT ;
    USE SIGNAL ;
    ANTENNAGATEAREA 6.753500 ;
    PORT
      LAYER Metal2 ;
        RECT 205.720 0.000 206.120 0.400 ;
    END
  END FrameStrobe[18]
  PIN FrameStrobe[19]
    DIRECTION INPUT ;
    USE SIGNAL ;
    ANTENNAGATEAREA 5.110300 ;
    PORT
      LAYER Metal2 ;
        RECT 206.680 0.000 207.080 0.400 ;
    END
  END FrameStrobe[19]
  PIN FrameStrobe[1]
    DIRECTION INPUT ;
    USE SIGNAL ;
    ANTENNAGATEAREA 6.137300 ;
    PORT
      LAYER Metal2 ;
        RECT 189.400 0.000 189.800 0.400 ;
    END
  END FrameStrobe[1]
  PIN FrameStrobe[2]
    DIRECTION INPUT ;
    USE SIGNAL ;
    ANTENNAGATEAREA 5.931900 ;
    PORT
      LAYER Metal2 ;
        RECT 190.360 0.000 190.760 0.400 ;
    END
  END FrameStrobe[2]
  PIN FrameStrobe[3]
    DIRECTION INPUT ;
    USE SIGNAL ;
    ANTENNAGATEAREA 6.548100 ;
    PORT
      LAYER Metal2 ;
        RECT 191.320 0.000 191.720 0.400 ;
    END
  END FrameStrobe[3]
  PIN FrameStrobe[4]
    DIRECTION INPUT ;
    USE SIGNAL ;
    ANTENNAGATEAREA 6.753500 ;
    PORT
      LAYER Metal2 ;
        RECT 192.280 0.000 192.680 0.400 ;
    END
  END FrameStrobe[4]
  PIN FrameStrobe[5]
    DIRECTION INPUT ;
    USE SIGNAL ;
    ANTENNAGATEAREA 6.753500 ;
    PORT
      LAYER Metal2 ;
        RECT 193.240 0.000 193.640 0.400 ;
    END
  END FrameStrobe[5]
  PIN FrameStrobe[6]
    DIRECTION INPUT ;
    USE SIGNAL ;
    ANTENNAGATEAREA 6.753500 ;
    PORT
      LAYER Metal2 ;
        RECT 194.200 0.000 194.600 0.400 ;
    END
  END FrameStrobe[6]
  PIN FrameStrobe[7]
    DIRECTION INPUT ;
    USE SIGNAL ;
    ANTENNAGATEAREA 6.753500 ;
    PORT
      LAYER Metal2 ;
        RECT 195.160 0.000 195.560 0.400 ;
    END
  END FrameStrobe[7]
  PIN FrameStrobe[8]
    DIRECTION INPUT ;
    USE SIGNAL ;
    ANTENNAGATEAREA 6.753500 ;
    PORT
      LAYER Metal2 ;
        RECT 196.120 0.000 196.520 0.400 ;
    END
  END FrameStrobe[8]
  PIN FrameStrobe[9]
    DIRECTION INPUT ;
    USE SIGNAL ;
    ANTENNAGATEAREA 6.753500 ;
    PORT
      LAYER Metal2 ;
        RECT 197.080 0.000 197.480 0.400 ;
    END
  END FrameStrobe[9]
  PIN FrameStrobe_O[0]
    DIRECTION OUTPUT ;
    USE SIGNAL ;
    ANTENNADIFFAREA 2.724000 ;
    PORT
      LAYER Metal2 ;
        RECT 188.440 214.640 188.840 215.040 ;
    END
  END FrameStrobe_O[0]
  PIN FrameStrobe_O[10]
    DIRECTION OUTPUT ;
    USE SIGNAL ;
    ANTENNADIFFAREA 2.724000 ;
    PORT
      LAYER Metal2 ;
        RECT 198.040 214.640 198.440 215.040 ;
    END
  END FrameStrobe_O[10]
  PIN FrameStrobe_O[11]
    DIRECTION OUTPUT ;
    USE SIGNAL ;
    ANTENNADIFFAREA 2.724000 ;
    PORT
      LAYER Metal2 ;
        RECT 199.000 214.640 199.400 215.040 ;
    END
  END FrameStrobe_O[11]
  PIN FrameStrobe_O[12]
    DIRECTION OUTPUT ;
    USE SIGNAL ;
    ANTENNADIFFAREA 2.724000 ;
    PORT
      LAYER Metal2 ;
        RECT 199.960 214.640 200.360 215.040 ;
    END
  END FrameStrobe_O[12]
  PIN FrameStrobe_O[13]
    DIRECTION OUTPUT ;
    USE SIGNAL ;
    ANTENNADIFFAREA 2.724000 ;
    PORT
      LAYER Metal2 ;
        RECT 200.920 214.640 201.320 215.040 ;
    END
  END FrameStrobe_O[13]
  PIN FrameStrobe_O[14]
    DIRECTION OUTPUT ;
    USE SIGNAL ;
    ANTENNADIFFAREA 2.724000 ;
    PORT
      LAYER Metal2 ;
        RECT 201.880 214.640 202.280 215.040 ;
    END
  END FrameStrobe_O[14]
  PIN FrameStrobe_O[15]
    DIRECTION OUTPUT ;
    USE SIGNAL ;
    ANTENNADIFFAREA 2.724000 ;
    PORT
      LAYER Metal2 ;
        RECT 202.840 214.640 203.240 215.040 ;
    END
  END FrameStrobe_O[15]
  PIN FrameStrobe_O[16]
    DIRECTION OUTPUT ;
    USE SIGNAL ;
    ANTENNADIFFAREA 2.724000 ;
    PORT
      LAYER Metal2 ;
        RECT 203.800 214.640 204.200 215.040 ;
    END
  END FrameStrobe_O[16]
  PIN FrameStrobe_O[17]
    DIRECTION OUTPUT ;
    USE SIGNAL ;
    ANTENNADIFFAREA 2.724000 ;
    PORT
      LAYER Metal2 ;
        RECT 204.760 214.640 205.160 215.040 ;
    END
  END FrameStrobe_O[17]
  PIN FrameStrobe_O[18]
    DIRECTION OUTPUT ;
    USE SIGNAL ;
    ANTENNADIFFAREA 2.724000 ;
    PORT
      LAYER Metal2 ;
        RECT 205.720 214.640 206.120 215.040 ;
    END
  END FrameStrobe_O[18]
  PIN FrameStrobe_O[19]
    DIRECTION OUTPUT ;
    USE SIGNAL ;
    ANTENNADIFFAREA 2.724000 ;
    PORT
      LAYER Metal2 ;
        RECT 206.680 214.640 207.080 215.040 ;
    END
  END FrameStrobe_O[19]
  PIN FrameStrobe_O[1]
    DIRECTION OUTPUT ;
    USE SIGNAL ;
    ANTENNADIFFAREA 2.724000 ;
    PORT
      LAYER Metal2 ;
        RECT 189.400 214.640 189.800 215.040 ;
    END
  END FrameStrobe_O[1]
  PIN FrameStrobe_O[2]
    DIRECTION OUTPUT ;
    USE SIGNAL ;
    ANTENNADIFFAREA 2.724000 ;
    PORT
      LAYER Metal2 ;
        RECT 190.360 214.640 190.760 215.040 ;
    END
  END FrameStrobe_O[2]
  PIN FrameStrobe_O[3]
    DIRECTION OUTPUT ;
    USE SIGNAL ;
    ANTENNADIFFAREA 2.724000 ;
    PORT
      LAYER Metal2 ;
        RECT 191.320 214.640 191.720 215.040 ;
    END
  END FrameStrobe_O[3]
  PIN FrameStrobe_O[4]
    DIRECTION OUTPUT ;
    USE SIGNAL ;
    ANTENNADIFFAREA 2.724000 ;
    PORT
      LAYER Metal2 ;
        RECT 192.280 214.640 192.680 215.040 ;
    END
  END FrameStrobe_O[4]
  PIN FrameStrobe_O[5]
    DIRECTION OUTPUT ;
    USE SIGNAL ;
    ANTENNADIFFAREA 2.724000 ;
    PORT
      LAYER Metal2 ;
        RECT 193.240 214.640 193.640 215.040 ;
    END
  END FrameStrobe_O[5]
  PIN FrameStrobe_O[6]
    DIRECTION OUTPUT ;
    USE SIGNAL ;
    ANTENNADIFFAREA 2.724000 ;
    PORT
      LAYER Metal2 ;
        RECT 194.200 214.640 194.600 215.040 ;
    END
  END FrameStrobe_O[6]
  PIN FrameStrobe_O[7]
    DIRECTION OUTPUT ;
    USE SIGNAL ;
    ANTENNADIFFAREA 2.724000 ;
    PORT
      LAYER Metal2 ;
        RECT 195.160 214.640 195.560 215.040 ;
    END
  END FrameStrobe_O[7]
  PIN FrameStrobe_O[8]
    DIRECTION OUTPUT ;
    USE SIGNAL ;
    ANTENNADIFFAREA 2.724000 ;
    PORT
      LAYER Metal2 ;
        RECT 196.120 214.640 196.520 215.040 ;
    END
  END FrameStrobe_O[8]
  PIN FrameStrobe_O[9]
    DIRECTION OUTPUT ;
    USE SIGNAL ;
    ANTENNADIFFAREA 2.724000 ;
    PORT
      LAYER Metal2 ;
        RECT 197.080 214.640 197.480 215.040 ;
    END
  END FrameStrobe_O[9]
  PIN N1BEG[0]
    DIRECTION OUTPUT ;
    USE SIGNAL ;
    ANTENNADIFFAREA 2.724000 ;
    PORT
      LAYER Metal2 ;
        RECT 2.200 214.640 2.600 215.040 ;
    END
  END N1BEG[0]
  PIN N1BEG[1]
    DIRECTION OUTPUT ;
    USE SIGNAL ;
    ANTENNADIFFAREA 2.724000 ;
    PORT
      LAYER Metal2 ;
        RECT 3.160 214.640 3.560 215.040 ;
    END
  END N1BEG[1]
  PIN N1BEG[2]
    DIRECTION OUTPUT ;
    USE SIGNAL ;
    ANTENNADIFFAREA 2.724000 ;
    PORT
      LAYER Metal2 ;
        RECT 4.120 214.640 4.520 215.040 ;
    END
  END N1BEG[2]
  PIN N1BEG[3]
    DIRECTION OUTPUT ;
    USE SIGNAL ;
    ANTENNADIFFAREA 2.724000 ;
    PORT
      LAYER Metal2 ;
        RECT 5.080 214.640 5.480 215.040 ;
    END
  END N1BEG[3]
  PIN N1END[0]
    DIRECTION INPUT ;
    USE SIGNAL ;
    ANTENNAGATEAREA 2.276600 ;
    PORT
      LAYER Metal2 ;
        RECT 2.200 0.000 2.600 0.400 ;
    END
  END N1END[0]
  PIN N1END[1]
    DIRECTION INPUT ;
    USE SIGNAL ;
    ANTENNAGATEAREA 2.169700 ;
    PORT
      LAYER Metal2 ;
        RECT 3.160 0.000 3.560 0.400 ;
    END
  END N1END[1]
  PIN N1END[2]
    DIRECTION INPUT ;
    USE SIGNAL ;
    ANTENNAGATEAREA 2.210800 ;
    PORT
      LAYER Metal2 ;
        RECT 4.120 0.000 4.520 0.400 ;
    END
  END N1END[2]
  PIN N1END[3]
    DIRECTION INPUT ;
    USE SIGNAL ;
    ANTENNAGATEAREA 2.132000 ;
    PORT
      LAYER Metal2 ;
        RECT 5.080 0.000 5.480 0.400 ;
    END
  END N1END[3]
  PIN N2BEG[0]
    DIRECTION OUTPUT ;
    USE SIGNAL ;
    ANTENNADIFFAREA 2.724000 ;
    PORT
      LAYER Metal2 ;
        RECT 10.840 214.640 11.240 215.040 ;
    END
  END N2BEG[0]
  PIN N2BEG[1]
    DIRECTION OUTPUT ;
    USE SIGNAL ;
    ANTENNADIFFAREA 2.724000 ;
    PORT
      LAYER Metal2 ;
        RECT 11.800 214.640 12.200 215.040 ;
    END
  END N2BEG[1]
  PIN N2BEG[2]
    DIRECTION OUTPUT ;
    USE SIGNAL ;
    ANTENNADIFFAREA 2.724000 ;
    PORT
      LAYER Metal2 ;
        RECT 12.760 214.640 13.160 215.040 ;
    END
  END N2BEG[2]
  PIN N2BEG[3]
    DIRECTION OUTPUT ;
    USE SIGNAL ;
    ANTENNADIFFAREA 2.724000 ;
    PORT
      LAYER Metal2 ;
        RECT 13.720 214.640 14.120 215.040 ;
    END
  END N2BEG[3]
  PIN N2BEG[4]
    DIRECTION OUTPUT ;
    USE SIGNAL ;
    ANTENNADIFFAREA 2.724000 ;
    PORT
      LAYER Metal2 ;
        RECT 14.680 214.640 15.080 215.040 ;
    END
  END N2BEG[4]
  PIN N2BEG[5]
    DIRECTION OUTPUT ;
    USE SIGNAL ;
    ANTENNADIFFAREA 2.724000 ;
    PORT
      LAYER Metal2 ;
        RECT 15.640 214.640 16.040 215.040 ;
    END
  END N2BEG[5]
  PIN N2BEG[6]
    DIRECTION OUTPUT ;
    USE SIGNAL ;
    ANTENNADIFFAREA 2.724000 ;
    PORT
      LAYER Metal2 ;
        RECT 16.600 214.640 17.000 215.040 ;
    END
  END N2BEG[6]
  PIN N2BEG[7]
    DIRECTION OUTPUT ;
    USE SIGNAL ;
    ANTENNADIFFAREA 2.724000 ;
    PORT
      LAYER Metal2 ;
        RECT 17.560 214.640 17.960 215.040 ;
    END
  END N2BEG[7]
  PIN N2BEGb[0]
    DIRECTION OUTPUT ;
    USE SIGNAL ;
    ANTENNADIFFAREA 2.724000 ;
    PORT
      LAYER Metal2 ;
        RECT 24.280 214.640 24.680 215.040 ;
    END
  END N2BEGb[0]
  PIN N2BEGb[1]
    DIRECTION OUTPUT ;
    USE SIGNAL ;
    ANTENNADIFFAREA 2.724000 ;
    PORT
      LAYER Metal2 ;
        RECT 25.240 214.640 25.640 215.040 ;
    END
  END N2BEGb[1]
  PIN N2BEGb[2]
    DIRECTION OUTPUT ;
    USE SIGNAL ;
    ANTENNADIFFAREA 2.724000 ;
    PORT
      LAYER Metal2 ;
        RECT 26.200 214.640 26.600 215.040 ;
    END
  END N2BEGb[2]
  PIN N2BEGb[3]
    DIRECTION OUTPUT ;
    USE SIGNAL ;
    ANTENNADIFFAREA 2.724000 ;
    PORT
      LAYER Metal2 ;
        RECT 27.160 214.640 27.560 215.040 ;
    END
  END N2BEGb[3]
  PIN N2BEGb[4]
    DIRECTION OUTPUT ;
    USE SIGNAL ;
    ANTENNADIFFAREA 2.724000 ;
    PORT
      LAYER Metal2 ;
        RECT 28.120 214.640 28.520 215.040 ;
    END
  END N2BEGb[4]
  PIN N2BEGb[5]
    DIRECTION OUTPUT ;
    USE SIGNAL ;
    ANTENNADIFFAREA 2.724000 ;
    PORT
      LAYER Metal2 ;
        RECT 29.080 214.640 29.480 215.040 ;
    END
  END N2BEGb[5]
  PIN N2BEGb[6]
    DIRECTION OUTPUT ;
    USE SIGNAL ;
    ANTENNADIFFAREA 2.724000 ;
    PORT
      LAYER Metal2 ;
        RECT 30.040 214.640 30.440 215.040 ;
    END
  END N2BEGb[6]
  PIN N2BEGb[7]
    DIRECTION OUTPUT ;
    USE SIGNAL ;
    ANTENNADIFFAREA 2.724000 ;
    PORT
      LAYER Metal2 ;
        RECT 31.000 214.640 31.400 215.040 ;
    END
  END N2BEGb[7]
  PIN N2END[0]
    DIRECTION INPUT ;
    USE SIGNAL ;
    ANTENNAGATEAREA 1.292200 ;
    PORT
      LAYER Metal2 ;
        RECT 24.280 0.000 24.680 0.400 ;
    END
  END N2END[0]
  PIN N2END[1]
    DIRECTION INPUT ;
    USE SIGNAL ;
    ANTENNAGATEAREA 1.079000 ;
    PORT
      LAYER Metal2 ;
        RECT 25.240 0.000 25.640 0.400 ;
    END
  END N2END[1]
  PIN N2END[2]
    DIRECTION INPUT ;
    USE SIGNAL ;
    ANTENNAGATEAREA 1.079000 ;
    PORT
      LAYER Metal2 ;
        RECT 26.200 0.000 26.600 0.400 ;
    END
  END N2END[2]
  PIN N2END[3]
    DIRECTION INPUT ;
    USE SIGNAL ;
    ANTENNAGATEAREA 1.349400 ;
    PORT
      LAYER Metal2 ;
        RECT 27.160 0.000 27.560 0.400 ;
    END
  END N2END[3]
  PIN N2END[4]
    DIRECTION INPUT ;
    USE SIGNAL ;
    ANTENNAGATEAREA 1.345000 ;
    PORT
      LAYER Metal2 ;
        RECT 28.120 0.000 28.520 0.400 ;
    END
  END N2END[4]
  PIN N2END[5]
    DIRECTION INPUT ;
    USE SIGNAL ;
    ANTENNAGATEAREA 1.046500 ;
    PORT
      LAYER Metal2 ;
        RECT 29.080 0.000 29.480 0.400 ;
    END
  END N2END[5]
  PIN N2END[6]
    DIRECTION INPUT ;
    USE SIGNAL ;
    ANTENNAGATEAREA 1.066000 ;
    PORT
      LAYER Metal2 ;
        RECT 30.040 0.000 30.440 0.400 ;
    END
  END N2END[6]
  PIN N2END[7]
    DIRECTION INPUT ;
    USE SIGNAL ;
    ANTENNAGATEAREA 1.279200 ;
    PORT
      LAYER Metal2 ;
        RECT 31.000 0.000 31.400 0.400 ;
    END
  END N2END[7]
  PIN N2MID[0]
    DIRECTION INPUT ;
    USE SIGNAL ;
    ANTENNAGATEAREA 0.833300 ;
    ANTENNADIFFAREA 8.061600 ;
    PORT
      LAYER Metal2 ;
        RECT 10.840 0.000 11.240 0.400 ;
    END
  END N2MID[0]
  PIN N2MID[1]
    DIRECTION INPUT ;
    USE SIGNAL ;
    ANTENNAGATEAREA 1.033500 ;
    PORT
      LAYER Metal2 ;
        RECT 11.800 0.000 12.200 0.400 ;
    END
  END N2MID[1]
  PIN N2MID[2]
    DIRECTION INPUT ;
    USE SIGNAL ;
    ANTENNAGATEAREA 0.820300 ;
    ANTENNADIFFAREA 32.246399 ;
    PORT
      LAYER Metal2 ;
        RECT 12.760 0.000 13.160 0.400 ;
    END
  END N2MID[2]
  PIN N2MID[3]
    DIRECTION INPUT ;
    USE SIGNAL ;
    ANTENNAGATEAREA 1.033500 ;
    PORT
      LAYER Metal2 ;
        RECT 13.720 0.000 14.120 0.400 ;
    END
  END N2MID[3]
  PIN N2MID[4]
    DIRECTION INPUT ;
    USE SIGNAL ;
    ANTENNAGATEAREA 0.820300 ;
    PORT
      LAYER Metal2 ;
        RECT 14.680 0.000 15.080 0.400 ;
    END
  END N2MID[4]
  PIN N2MID[5]
    DIRECTION INPUT ;
    USE SIGNAL ;
    ANTENNAGATEAREA 1.033500 ;
    ANTENNADIFFAREA 12.092400 ;
    PORT
      LAYER Metal2 ;
        RECT 15.640 0.000 16.040 0.400 ;
    END
  END N2MID[5]
  PIN N2MID[6]
    DIRECTION INPUT ;
    USE SIGNAL ;
    ANTENNAGATEAREA 0.820300 ;
    ANTENNADIFFAREA 10.077000 ;
    PORT
      LAYER Metal2 ;
        RECT 16.600 0.000 17.000 0.400 ;
    END
  END N2MID[6]
  PIN N2MID[7]
    DIRECTION INPUT ;
    USE SIGNAL ;
    ANTENNAGATEAREA 1.033500 ;
    PORT
      LAYER Metal2 ;
        RECT 17.560 0.000 17.960 0.400 ;
    END
  END N2MID[7]
  PIN N4BEG[0]
    DIRECTION OUTPUT ;
    USE SIGNAL ;
    ANTENNADIFFAREA 2.724000 ;
    PORT
      LAYER Metal2 ;
        RECT 40.600 214.640 41.000 215.040 ;
    END
  END N4BEG[0]
  PIN N4BEG[10]
    DIRECTION OUTPUT ;
    USE SIGNAL ;
    ANTENNADIFFAREA 2.724000 ;
    PORT
      LAYER Metal2 ;
        RECT 50.200 214.640 50.600 215.040 ;
    END
  END N4BEG[10]
  PIN N4BEG[11]
    DIRECTION OUTPUT ;
    USE SIGNAL ;
    ANTENNADIFFAREA 2.724000 ;
    PORT
      LAYER Metal2 ;
        RECT 51.160 214.640 51.560 215.040 ;
    END
  END N4BEG[11]
  PIN N4BEG[12]
    DIRECTION OUTPUT ;
    USE SIGNAL ;
    ANTENNADIFFAREA 2.724000 ;
    PORT
      LAYER Metal2 ;
        RECT 52.120 214.640 52.520 215.040 ;
    END
  END N4BEG[12]
  PIN N4BEG[13]
    DIRECTION OUTPUT ;
    USE SIGNAL ;
    ANTENNADIFFAREA 2.724000 ;
    PORT
      LAYER Metal2 ;
        RECT 53.080 214.640 53.480 215.040 ;
    END
  END N4BEG[13]
  PIN N4BEG[14]
    DIRECTION OUTPUT ;
    USE SIGNAL ;
    ANTENNADIFFAREA 2.724000 ;
    PORT
      LAYER Metal2 ;
        RECT 54.040 214.640 54.440 215.040 ;
    END
  END N4BEG[14]
  PIN N4BEG[15]
    DIRECTION OUTPUT ;
    USE SIGNAL ;
    ANTENNADIFFAREA 2.724000 ;
    PORT
      LAYER Metal2 ;
        RECT 55.000 214.640 55.400 215.040 ;
    END
  END N4BEG[15]
  PIN N4BEG[1]
    DIRECTION OUTPUT ;
    USE SIGNAL ;
    ANTENNADIFFAREA 2.724000 ;
    PORT
      LAYER Metal2 ;
        RECT 41.560 214.640 41.960 215.040 ;
    END
  END N4BEG[1]
  PIN N4BEG[2]
    DIRECTION OUTPUT ;
    USE SIGNAL ;
    ANTENNADIFFAREA 2.724000 ;
    PORT
      LAYER Metal2 ;
        RECT 42.520 214.640 42.920 215.040 ;
    END
  END N4BEG[2]
  PIN N4BEG[3]
    DIRECTION OUTPUT ;
    USE SIGNAL ;
    ANTENNADIFFAREA 2.724000 ;
    PORT
      LAYER Metal2 ;
        RECT 43.480 214.640 43.880 215.040 ;
    END
  END N4BEG[3]
  PIN N4BEG[4]
    DIRECTION OUTPUT ;
    USE SIGNAL ;
    ANTENNADIFFAREA 2.724000 ;
    PORT
      LAYER Metal2 ;
        RECT 44.440 214.640 44.840 215.040 ;
    END
  END N4BEG[4]
  PIN N4BEG[5]
    DIRECTION OUTPUT ;
    USE SIGNAL ;
    ANTENNADIFFAREA 2.724000 ;
    PORT
      LAYER Metal2 ;
        RECT 45.400 214.640 45.800 215.040 ;
    END
  END N4BEG[5]
  PIN N4BEG[6]
    DIRECTION OUTPUT ;
    USE SIGNAL ;
    ANTENNADIFFAREA 2.724000 ;
    PORT
      LAYER Metal2 ;
        RECT 46.360 214.640 46.760 215.040 ;
    END
  END N4BEG[6]
  PIN N4BEG[7]
    DIRECTION OUTPUT ;
    USE SIGNAL ;
    ANTENNADIFFAREA 2.724000 ;
    PORT
      LAYER Metal2 ;
        RECT 47.320 214.640 47.720 215.040 ;
    END
  END N4BEG[7]
  PIN N4BEG[8]
    DIRECTION OUTPUT ;
    USE SIGNAL ;
    ANTENNADIFFAREA 2.724000 ;
    PORT
      LAYER Metal2 ;
        RECT 48.280 214.640 48.680 215.040 ;
    END
  END N4BEG[8]
  PIN N4BEG[9]
    DIRECTION OUTPUT ;
    USE SIGNAL ;
    ANTENNADIFFAREA 2.724000 ;
    PORT
      LAYER Metal2 ;
        RECT 49.240 214.640 49.640 215.040 ;
    END
  END N4BEG[9]
  PIN N4END[0]
    DIRECTION INPUT ;
    USE SIGNAL ;
    ANTENNAGATEAREA 1.079000 ;
    PORT
      LAYER Metal2 ;
        RECT 40.600 0.000 41.000 0.400 ;
    END
  END N4END[0]
  PIN N4END[10]
    DIRECTION INPUT ;
    USE SIGNAL ;
    ANTENNAGATEAREA 0.180700 ;
    PORT
      LAYER Metal2 ;
        RECT 50.200 0.000 50.600 0.400 ;
    END
  END N4END[10]
  PIN N4END[11]
    DIRECTION INPUT ;
    USE SIGNAL ;
    ANTENNAGATEAREA 0.180700 ;
    PORT
      LAYER Metal2 ;
        RECT 51.160 0.000 51.560 0.400 ;
    END
  END N4END[11]
  PIN N4END[12]
    DIRECTION INPUT ;
    USE SIGNAL ;
    ANTENNAGATEAREA 0.180700 ;
    PORT
      LAYER Metal2 ;
        RECT 52.120 0.000 52.520 0.400 ;
    END
  END N4END[12]
  PIN N4END[13]
    DIRECTION INPUT ;
    USE SIGNAL ;
    ANTENNAGATEAREA 0.180700 ;
    PORT
      LAYER Metal2 ;
        RECT 53.080 0.000 53.480 0.400 ;
    END
  END N4END[13]
  PIN N4END[14]
    DIRECTION INPUT ;
    USE SIGNAL ;
    ANTENNAGATEAREA 0.180700 ;
    PORT
      LAYER Metal2 ;
        RECT 54.040 0.000 54.440 0.400 ;
    END
  END N4END[14]
  PIN N4END[15]
    DIRECTION INPUT ;
    USE SIGNAL ;
    ANTENNAGATEAREA 0.180700 ;
    PORT
      LAYER Metal2 ;
        RECT 55.000 0.000 55.400 0.400 ;
    END
  END N4END[15]
  PIN N4END[1]
    DIRECTION INPUT ;
    USE SIGNAL ;
    ANTENNAGATEAREA 1.079000 ;
    PORT
      LAYER Metal2 ;
        RECT 41.560 0.000 41.960 0.400 ;
    END
  END N4END[1]
  PIN N4END[2]
    DIRECTION INPUT ;
    USE SIGNAL ;
    ANTENNAGATEAREA 1.079000 ;
    PORT
      LAYER Metal2 ;
        RECT 42.520 0.000 42.920 0.400 ;
    END
  END N4END[2]
  PIN N4END[3]
    DIRECTION INPUT ;
    USE SIGNAL ;
    ANTENNAGATEAREA 1.092000 ;
    PORT
      LAYER Metal2 ;
        RECT 43.480 0.000 43.880 0.400 ;
    END
  END N4END[3]
  PIN N4END[4]
    DIRECTION INPUT ;
    USE SIGNAL ;
    ANTENNAGATEAREA 0.180700 ;
    PORT
      LAYER Metal2 ;
        RECT 44.440 0.000 44.840 0.400 ;
    END
  END N4END[4]
  PIN N4END[5]
    DIRECTION INPUT ;
    USE SIGNAL ;
    ANTENNAGATEAREA 0.180700 ;
    PORT
      LAYER Metal2 ;
        RECT 45.400 0.000 45.800 0.400 ;
    END
  END N4END[5]
  PIN N4END[6]
    DIRECTION INPUT ;
    USE SIGNAL ;
    ANTENNAGATEAREA 0.180700 ;
    ANTENNADIFFAREA 2.015400 ;
    PORT
      LAYER Metal2 ;
        RECT 46.360 0.000 46.760 0.400 ;
    END
  END N4END[6]
  PIN N4END[7]
    DIRECTION INPUT ;
    USE SIGNAL ;
    ANTENNAGATEAREA 0.180700 ;
    PORT
      LAYER Metal2 ;
        RECT 47.320 0.000 47.720 0.400 ;
    END
  END N4END[7]
  PIN N4END[8]
    DIRECTION INPUT ;
    USE SIGNAL ;
    ANTENNAGATEAREA 0.180700 ;
    PORT
      LAYER Metal2 ;
        RECT 48.280 0.000 48.680 0.400 ;
    END
  END N4END[8]
  PIN N4END[9]
    DIRECTION INPUT ;
    USE SIGNAL ;
    ANTENNAGATEAREA 0.180700 ;
    PORT
      LAYER Metal2 ;
        RECT 49.240 0.000 49.640 0.400 ;
    END
  END N4END[9]
  PIN NN4BEG[0]
    DIRECTION OUTPUT ;
    USE SIGNAL ;
    ANTENNADIFFAREA 2.724000 ;
    PORT
      LAYER Metal2 ;
        RECT 68.440 214.640 68.840 215.040 ;
    END
  END NN4BEG[0]
  PIN NN4BEG[10]
    DIRECTION OUTPUT ;
    USE SIGNAL ;
    ANTENNADIFFAREA 2.724000 ;
    PORT
      LAYER Metal2 ;
        RECT 78.040 214.640 78.440 215.040 ;
    END
  END NN4BEG[10]
  PIN NN4BEG[11]
    DIRECTION OUTPUT ;
    USE SIGNAL ;
    ANTENNADIFFAREA 2.724000 ;
    PORT
      LAYER Metal2 ;
        RECT 79.000 214.640 79.400 215.040 ;
    END
  END NN4BEG[11]
  PIN NN4BEG[12]
    DIRECTION OUTPUT ;
    USE SIGNAL ;
    ANTENNADIFFAREA 2.724000 ;
    PORT
      LAYER Metal2 ;
        RECT 79.960 214.640 80.360 215.040 ;
    END
  END NN4BEG[12]
  PIN NN4BEG[13]
    DIRECTION OUTPUT ;
    USE SIGNAL ;
    ANTENNADIFFAREA 2.724000 ;
    PORT
      LAYER Metal2 ;
        RECT 80.920 214.640 81.320 215.040 ;
    END
  END NN4BEG[13]
  PIN NN4BEG[14]
    DIRECTION OUTPUT ;
    USE SIGNAL ;
    ANTENNADIFFAREA 2.724000 ;
    PORT
      LAYER Metal2 ;
        RECT 81.880 214.640 82.280 215.040 ;
    END
  END NN4BEG[14]
  PIN NN4BEG[15]
    DIRECTION OUTPUT ;
    USE SIGNAL ;
    ANTENNADIFFAREA 2.724000 ;
    PORT
      LAYER Metal2 ;
        RECT 82.840 214.640 83.240 215.040 ;
    END
  END NN4BEG[15]
  PIN NN4BEG[1]
    DIRECTION OUTPUT ;
    USE SIGNAL ;
    ANTENNADIFFAREA 2.724000 ;
    PORT
      LAYER Metal2 ;
        RECT 69.400 214.640 69.800 215.040 ;
    END
  END NN4BEG[1]
  PIN NN4BEG[2]
    DIRECTION OUTPUT ;
    USE SIGNAL ;
    ANTENNADIFFAREA 2.724000 ;
    PORT
      LAYER Metal2 ;
        RECT 70.360 214.640 70.760 215.040 ;
    END
  END NN4BEG[2]
  PIN NN4BEG[3]
    DIRECTION OUTPUT ;
    USE SIGNAL ;
    ANTENNADIFFAREA 2.724000 ;
    PORT
      LAYER Metal2 ;
        RECT 71.320 214.640 71.720 215.040 ;
    END
  END NN4BEG[3]
  PIN NN4BEG[4]
    DIRECTION OUTPUT ;
    USE SIGNAL ;
    ANTENNADIFFAREA 2.724000 ;
    PORT
      LAYER Metal2 ;
        RECT 72.280 214.640 72.680 215.040 ;
    END
  END NN4BEG[4]
  PIN NN4BEG[5]
    DIRECTION OUTPUT ;
    USE SIGNAL ;
    ANTENNADIFFAREA 2.724000 ;
    PORT
      LAYER Metal2 ;
        RECT 73.240 214.640 73.640 215.040 ;
    END
  END NN4BEG[5]
  PIN NN4BEG[6]
    DIRECTION OUTPUT ;
    USE SIGNAL ;
    ANTENNADIFFAREA 2.724000 ;
    PORT
      LAYER Metal2 ;
        RECT 74.200 214.640 74.600 215.040 ;
    END
  END NN4BEG[6]
  PIN NN4BEG[7]
    DIRECTION OUTPUT ;
    USE SIGNAL ;
    ANTENNADIFFAREA 2.724000 ;
    PORT
      LAYER Metal2 ;
        RECT 75.160 214.640 75.560 215.040 ;
    END
  END NN4BEG[7]
  PIN NN4BEG[8]
    DIRECTION OUTPUT ;
    USE SIGNAL ;
    ANTENNADIFFAREA 2.724000 ;
    PORT
      LAYER Metal2 ;
        RECT 76.120 214.640 76.520 215.040 ;
    END
  END NN4BEG[8]
  PIN NN4BEG[9]
    DIRECTION OUTPUT ;
    USE SIGNAL ;
    ANTENNADIFFAREA 2.724000 ;
    PORT
      LAYER Metal2 ;
        RECT 77.080 214.640 77.480 215.040 ;
    END
  END NN4BEG[9]
  PIN NN4END[0]
    DIRECTION INPUT ;
    USE SIGNAL ;
    ANTENNAGATEAREA 0.652600 ;
    PORT
      LAYER Metal2 ;
        RECT 68.440 0.000 68.840 0.400 ;
    END
  END NN4END[0]
  PIN NN4END[10]
    DIRECTION INPUT ;
    USE SIGNAL ;
    ANTENNAGATEAREA 0.180700 ;
    PORT
      LAYER Metal2 ;
        RECT 78.040 0.000 78.440 0.400 ;
    END
  END NN4END[10]
  PIN NN4END[11]
    DIRECTION INPUT ;
    USE SIGNAL ;
    ANTENNAGATEAREA 0.180700 ;
    PORT
      LAYER Metal2 ;
        RECT 79.000 0.000 79.400 0.400 ;
    END
  END NN4END[11]
  PIN NN4END[12]
    DIRECTION INPUT ;
    USE SIGNAL ;
    ANTENNAGATEAREA 0.180700 ;
    PORT
      LAYER Metal2 ;
        RECT 79.960 0.000 80.360 0.400 ;
    END
  END NN4END[12]
  PIN NN4END[13]
    DIRECTION INPUT ;
    USE SIGNAL ;
    ANTENNAGATEAREA 0.180700 ;
    PORT
      LAYER Metal2 ;
        RECT 80.920 0.000 81.320 0.400 ;
    END
  END NN4END[13]
  PIN NN4END[14]
    DIRECTION INPUT ;
    USE SIGNAL ;
    ANTENNAGATEAREA 0.180700 ;
    PORT
      LAYER Metal2 ;
        RECT 81.880 0.000 82.280 0.400 ;
    END
  END NN4END[14]
  PIN NN4END[15]
    DIRECTION INPUT ;
    USE SIGNAL ;
    ANTENNAGATEAREA 0.180700 ;
    PORT
      LAYER Metal2 ;
        RECT 82.840 0.000 83.240 0.400 ;
    END
  END NN4END[15]
  PIN NN4END[1]
    DIRECTION INPUT ;
    USE SIGNAL ;
    ANTENNAGATEAREA 0.639600 ;
    PORT
      LAYER Metal2 ;
        RECT 69.400 0.000 69.800 0.400 ;
    END
  END NN4END[1]
  PIN NN4END[2]
    DIRECTION INPUT ;
    USE SIGNAL ;
    ANTENNAGATEAREA 0.668200 ;
    PORT
      LAYER Metal2 ;
        RECT 70.360 0.000 70.760 0.400 ;
    END
  END NN4END[2]
  PIN NN4END[3]
    DIRECTION INPUT ;
    USE SIGNAL ;
    ANTENNAGATEAREA 0.652600 ;
    PORT
      LAYER Metal2 ;
        RECT 71.320 0.000 71.720 0.400 ;
    END
  END NN4END[3]
  PIN NN4END[4]
    DIRECTION INPUT ;
    USE SIGNAL ;
    ANTENNAGATEAREA 0.180700 ;
    PORT
      LAYER Metal2 ;
        RECT 72.280 0.000 72.680 0.400 ;
    END
  END NN4END[4]
  PIN NN4END[5]
    DIRECTION INPUT ;
    USE SIGNAL ;
    ANTENNAGATEAREA 0.180700 ;
    PORT
      LAYER Metal2 ;
        RECT 73.240 0.000 73.640 0.400 ;
    END
  END NN4END[5]
  PIN NN4END[6]
    DIRECTION INPUT ;
    USE SIGNAL ;
    ANTENNAGATEAREA 0.180700 ;
    PORT
      LAYER Metal2 ;
        RECT 74.200 0.000 74.600 0.400 ;
    END
  END NN4END[6]
  PIN NN4END[7]
    DIRECTION INPUT ;
    USE SIGNAL ;
    ANTENNAGATEAREA 0.180700 ;
    PORT
      LAYER Metal2 ;
        RECT 75.160 0.000 75.560 0.400 ;
    END
  END NN4END[7]
  PIN NN4END[8]
    DIRECTION INPUT ;
    USE SIGNAL ;
    ANTENNAGATEAREA 0.180700 ;
    PORT
      LAYER Metal2 ;
        RECT 76.120 0.000 76.520 0.400 ;
    END
  END NN4END[8]
  PIN NN4END[9]
    DIRECTION INPUT ;
    USE SIGNAL ;
    ANTENNAGATEAREA 0.180700 ;
    PORT
      LAYER Metal2 ;
        RECT 77.080 0.000 77.480 0.400 ;
    END
  END NN4END[9]
  PIN S1BEG[0]
    DIRECTION OUTPUT ;
    USE SIGNAL ;
    ANTENNADIFFAREA 2.724000 ;
    PORT
      LAYER Metal2 ;
        RECT 90.520 0.000 90.920 0.400 ;
    END
  END S1BEG[0]
  PIN S1BEG[1]
    DIRECTION OUTPUT ;
    USE SIGNAL ;
    ANTENNADIFFAREA 2.724000 ;
    PORT
      LAYER Metal2 ;
        RECT 91.480 0.000 91.880 0.400 ;
    END
  END S1BEG[1]
  PIN S1BEG[2]
    DIRECTION OUTPUT ;
    USE SIGNAL ;
    ANTENNADIFFAREA 2.724000 ;
    PORT
      LAYER Metal2 ;
        RECT 92.440 0.000 92.840 0.400 ;
    END
  END S1BEG[2]
  PIN S1BEG[3]
    DIRECTION OUTPUT ;
    USE SIGNAL ;
    ANTENNADIFFAREA 2.724000 ;
    PORT
      LAYER Metal2 ;
        RECT 93.400 0.000 93.800 0.400 ;
    END
  END S1BEG[3]
  PIN S1END[0]
    DIRECTION INPUT ;
    USE SIGNAL ;
    ANTENNAGATEAREA 1.705600 ;
    ANTENNADIFFAREA 16.123199 ;
    PORT
      LAYER Metal2 ;
        RECT 90.520 214.640 90.920 215.040 ;
    END
  END S1END[0]
  PIN S1END[1]
    DIRECTION INPUT ;
    USE SIGNAL ;
    ANTENNAGATEAREA 1.747200 ;
    PORT
      LAYER Metal2 ;
        RECT 91.480 214.640 91.880 215.040 ;
    END
  END S1END[1]
  PIN S1END[2]
    DIRECTION INPUT ;
    USE SIGNAL ;
    ANTENNAGATEAREA 1.734200 ;
    PORT
      LAYER Metal2 ;
        RECT 92.440 214.640 92.840 215.040 ;
    END
  END S1END[2]
  PIN S1END[3]
    DIRECTION INPUT ;
    USE SIGNAL ;
    ANTENNAGATEAREA 1.718600 ;
    PORT
      LAYER Metal2 ;
        RECT 93.400 214.640 93.800 215.040 ;
    END
  END S1END[3]
  PIN S2BEG[0]
    DIRECTION OUTPUT ;
    USE SIGNAL ;
    ANTENNADIFFAREA 2.724000 ;
    PORT
      LAYER Metal2 ;
        RECT 99.160 0.000 99.560 0.400 ;
    END
  END S2BEG[0]
  PIN S2BEG[1]
    DIRECTION OUTPUT ;
    USE SIGNAL ;
    ANTENNADIFFAREA 2.724000 ;
    PORT
      LAYER Metal2 ;
        RECT 100.120 0.000 100.520 0.400 ;
    END
  END S2BEG[1]
  PIN S2BEG[2]
    DIRECTION OUTPUT ;
    USE SIGNAL ;
    ANTENNADIFFAREA 2.724000 ;
    PORT
      LAYER Metal2 ;
        RECT 101.080 0.000 101.480 0.400 ;
    END
  END S2BEG[2]
  PIN S2BEG[3]
    DIRECTION OUTPUT ;
    USE SIGNAL ;
    ANTENNADIFFAREA 2.724000 ;
    PORT
      LAYER Metal2 ;
        RECT 102.040 0.000 102.440 0.400 ;
    END
  END S2BEG[3]
  PIN S2BEG[4]
    DIRECTION OUTPUT ;
    USE SIGNAL ;
    ANTENNADIFFAREA 2.724000 ;
    PORT
      LAYER Metal2 ;
        RECT 103.000 0.000 103.400 0.400 ;
    END
  END S2BEG[4]
  PIN S2BEG[5]
    DIRECTION OUTPUT ;
    USE SIGNAL ;
    ANTENNADIFFAREA 2.724000 ;
    PORT
      LAYER Metal2 ;
        RECT 103.960 0.000 104.360 0.400 ;
    END
  END S2BEG[5]
  PIN S2BEG[6]
    DIRECTION OUTPUT ;
    USE SIGNAL ;
    ANTENNADIFFAREA 2.724000 ;
    PORT
      LAYER Metal2 ;
        RECT 104.920 0.000 105.320 0.400 ;
    END
  END S2BEG[6]
  PIN S2BEG[7]
    DIRECTION OUTPUT ;
    USE SIGNAL ;
    ANTENNADIFFAREA 2.724000 ;
    PORT
      LAYER Metal2 ;
        RECT 105.880 0.000 106.280 0.400 ;
    END
  END S2BEG[7]
  PIN S2BEGb[0]
    DIRECTION OUTPUT ;
    USE SIGNAL ;
    ANTENNADIFFAREA 2.724000 ;
    PORT
      LAYER Metal2 ;
        RECT 112.600 0.000 113.000 0.400 ;
    END
  END S2BEGb[0]
  PIN S2BEGb[1]
    DIRECTION OUTPUT ;
    USE SIGNAL ;
    ANTENNADIFFAREA 2.724000 ;
    PORT
      LAYER Metal2 ;
        RECT 113.560 0.000 113.960 0.400 ;
    END
  END S2BEGb[1]
  PIN S2BEGb[2]
    DIRECTION OUTPUT ;
    USE SIGNAL ;
    ANTENNADIFFAREA 2.724000 ;
    PORT
      LAYER Metal2 ;
        RECT 114.520 0.000 114.920 0.400 ;
    END
  END S2BEGb[2]
  PIN S2BEGb[3]
    DIRECTION OUTPUT ;
    USE SIGNAL ;
    ANTENNADIFFAREA 2.724000 ;
    PORT
      LAYER Metal2 ;
        RECT 115.480 0.000 115.880 0.400 ;
    END
  END S2BEGb[3]
  PIN S2BEGb[4]
    DIRECTION OUTPUT ;
    USE SIGNAL ;
    ANTENNADIFFAREA 2.724000 ;
    PORT
      LAYER Metal2 ;
        RECT 116.440 0.000 116.840 0.400 ;
    END
  END S2BEGb[4]
  PIN S2BEGb[5]
    DIRECTION OUTPUT ;
    USE SIGNAL ;
    ANTENNADIFFAREA 2.724000 ;
    PORT
      LAYER Metal2 ;
        RECT 117.400 0.000 117.800 0.400 ;
    END
  END S2BEGb[5]
  PIN S2BEGb[6]
    DIRECTION OUTPUT ;
    USE SIGNAL ;
    ANTENNADIFFAREA 2.724000 ;
    PORT
      LAYER Metal2 ;
        RECT 118.360 0.000 118.760 0.400 ;
    END
  END S2BEGb[6]
  PIN S2BEGb[7]
    DIRECTION OUTPUT ;
    USE SIGNAL ;
    ANTENNADIFFAREA 2.724000 ;
    PORT
      LAYER Metal2 ;
        RECT 119.320 0.000 119.720 0.400 ;
    END
  END S2BEGb[7]
  PIN S2END[0]
    DIRECTION INPUT ;
    USE SIGNAL ;
    ANTENNAGATEAREA 1.320800 ;
    PORT
      LAYER Metal2 ;
        RECT 112.600 214.640 113.000 215.040 ;
    END
  END S2END[0]
  PIN S2END[1]
    DIRECTION INPUT ;
    USE SIGNAL ;
    ANTENNAGATEAREA 1.307800 ;
    PORT
      LAYER Metal2 ;
        RECT 113.560 214.640 113.960 215.040 ;
    END
  END S2END[1]
  PIN S2END[2]
    DIRECTION INPUT ;
    USE SIGNAL ;
    ANTENNAGATEAREA 1.320800 ;
    PORT
      LAYER Metal2 ;
        RECT 114.520 214.640 114.920 215.040 ;
    END
  END S2END[2]
  PIN S2END[3]
    DIRECTION INPUT ;
    USE SIGNAL ;
    ANTENNAGATEAREA 1.071200 ;
    PORT
      LAYER Metal2 ;
        RECT 115.480 214.640 115.880 215.040 ;
    END
  END S2END[3]
  PIN S2END[4]
    DIRECTION INPUT ;
    USE SIGNAL ;
    ANTENNAGATEAREA 1.079000 ;
    PORT
      LAYER Metal2 ;
        RECT 116.440 214.640 116.840 215.040 ;
    END
  END S2END[4]
  PIN S2END[5]
    DIRECTION INPUT ;
    USE SIGNAL ;
    ANTENNAGATEAREA 1.173400 ;
    PORT
      LAYER Metal2 ;
        RECT 117.400 214.640 117.800 215.040 ;
    END
  END S2END[5]
  PIN S2END[6]
    DIRECTION INPUT ;
    USE SIGNAL ;
    ANTENNAGATEAREA 1.079000 ;
    PORT
      LAYER Metal2 ;
        RECT 118.360 214.640 118.760 215.040 ;
    END
  END S2END[6]
  PIN S2END[7]
    DIRECTION INPUT ;
    USE SIGNAL ;
    ANTENNAGATEAREA 1.305200 ;
    PORT
      LAYER Metal2 ;
        RECT 119.320 214.640 119.720 215.040 ;
    END
  END S2END[7]
  PIN S2MID[0]
    DIRECTION INPUT ;
    USE SIGNAL ;
    ANTENNAGATEAREA 0.833300 ;
    PORT
      LAYER Metal2 ;
        RECT 99.160 214.640 99.560 215.040 ;
    END
  END S2MID[0]
  PIN S2MID[1]
    DIRECTION INPUT ;
    USE SIGNAL ;
    ANTENNAGATEAREA 1.033500 ;
    PORT
      LAYER Metal2 ;
        RECT 100.120 214.640 100.520 215.040 ;
    END
  END S2MID[1]
  PIN S2MID[2]
    DIRECTION INPUT ;
    USE SIGNAL ;
    ANTENNAGATEAREA 0.848900 ;
    PORT
      LAYER Metal2 ;
        RECT 101.080 214.640 101.480 215.040 ;
    END
  END S2MID[2]
  PIN S2MID[3]
    DIRECTION INPUT ;
    USE SIGNAL ;
    ANTENNAGATEAREA 1.033500 ;
    PORT
      LAYER Metal2 ;
        RECT 102.040 214.640 102.440 215.040 ;
    END
  END S2MID[3]
  PIN S2MID[4]
    DIRECTION INPUT ;
    USE SIGNAL ;
    ANTENNAGATEAREA 0.820300 ;
    PORT
      LAYER Metal2 ;
        RECT 103.000 214.640 103.400 215.040 ;
    END
  END S2MID[4]
  PIN S2MID[5]
    DIRECTION INPUT ;
    USE SIGNAL ;
    ANTENNAGATEAREA 1.033500 ;
    PORT
      LAYER Metal2 ;
        RECT 103.960 214.640 104.360 215.040 ;
    END
  END S2MID[5]
  PIN S2MID[6]
    DIRECTION INPUT ;
    USE SIGNAL ;
    ANTENNAGATEAREA 0.820300 ;
    PORT
      LAYER Metal2 ;
        RECT 104.920 214.640 105.320 215.040 ;
    END
  END S2MID[6]
  PIN S2MID[7]
    DIRECTION INPUT ;
    USE SIGNAL ;
    ANTENNAGATEAREA 1.033500 ;
    PORT
      LAYER Metal2 ;
        RECT 105.880 214.640 106.280 215.040 ;
    END
  END S2MID[7]
  PIN S4BEG[0]
    DIRECTION OUTPUT ;
    USE SIGNAL ;
    ANTENNADIFFAREA 2.724000 ;
    PORT
      LAYER Metal2 ;
        RECT 128.920 0.000 129.320 0.400 ;
    END
  END S4BEG[0]
  PIN S4BEG[10]
    DIRECTION OUTPUT ;
    USE SIGNAL ;
    ANTENNADIFFAREA 2.724000 ;
    PORT
      LAYER Metal2 ;
        RECT 138.520 0.000 138.920 0.400 ;
    END
  END S4BEG[10]
  PIN S4BEG[11]
    DIRECTION OUTPUT ;
    USE SIGNAL ;
    ANTENNADIFFAREA 2.724000 ;
    PORT
      LAYER Metal2 ;
        RECT 139.480 0.000 139.880 0.400 ;
    END
  END S4BEG[11]
  PIN S4BEG[12]
    DIRECTION OUTPUT ;
    USE SIGNAL ;
    ANTENNADIFFAREA 2.724000 ;
    PORT
      LAYER Metal2 ;
        RECT 140.440 0.000 140.840 0.400 ;
    END
  END S4BEG[12]
  PIN S4BEG[13]
    DIRECTION OUTPUT ;
    USE SIGNAL ;
    ANTENNADIFFAREA 2.724000 ;
    PORT
      LAYER Metal2 ;
        RECT 141.400 0.000 141.800 0.400 ;
    END
  END S4BEG[13]
  PIN S4BEG[14]
    DIRECTION OUTPUT ;
    USE SIGNAL ;
    ANTENNADIFFAREA 2.724000 ;
    PORT
      LAYER Metal2 ;
        RECT 142.360 0.000 142.760 0.400 ;
    END
  END S4BEG[14]
  PIN S4BEG[15]
    DIRECTION OUTPUT ;
    USE SIGNAL ;
    ANTENNADIFFAREA 2.724000 ;
    PORT
      LAYER Metal2 ;
        RECT 143.320 0.000 143.720 0.400 ;
    END
  END S4BEG[15]
  PIN S4BEG[1]
    DIRECTION OUTPUT ;
    USE SIGNAL ;
    ANTENNADIFFAREA 2.724000 ;
    PORT
      LAYER Metal2 ;
        RECT 129.880 0.000 130.280 0.400 ;
    END
  END S4BEG[1]
  PIN S4BEG[2]
    DIRECTION OUTPUT ;
    USE SIGNAL ;
    ANTENNADIFFAREA 2.724000 ;
    PORT
      LAYER Metal2 ;
        RECT 130.840 0.000 131.240 0.400 ;
    END
  END S4BEG[2]
  PIN S4BEG[3]
    DIRECTION OUTPUT ;
    USE SIGNAL ;
    ANTENNADIFFAREA 2.724000 ;
    PORT
      LAYER Metal2 ;
        RECT 131.800 0.000 132.200 0.400 ;
    END
  END S4BEG[3]
  PIN S4BEG[4]
    DIRECTION OUTPUT ;
    USE SIGNAL ;
    ANTENNADIFFAREA 2.724000 ;
    PORT
      LAYER Metal2 ;
        RECT 132.760 0.000 133.160 0.400 ;
    END
  END S4BEG[4]
  PIN S4BEG[5]
    DIRECTION OUTPUT ;
    USE SIGNAL ;
    ANTENNADIFFAREA 2.724000 ;
    PORT
      LAYER Metal2 ;
        RECT 133.720 0.000 134.120 0.400 ;
    END
  END S4BEG[5]
  PIN S4BEG[6]
    DIRECTION OUTPUT ;
    USE SIGNAL ;
    ANTENNADIFFAREA 2.724000 ;
    PORT
      LAYER Metal2 ;
        RECT 134.680 0.000 135.080 0.400 ;
    END
  END S4BEG[6]
  PIN S4BEG[7]
    DIRECTION OUTPUT ;
    USE SIGNAL ;
    ANTENNADIFFAREA 2.724000 ;
    PORT
      LAYER Metal2 ;
        RECT 135.640 0.000 136.040 0.400 ;
    END
  END S4BEG[7]
  PIN S4BEG[8]
    DIRECTION OUTPUT ;
    USE SIGNAL ;
    ANTENNADIFFAREA 2.724000 ;
    PORT
      LAYER Metal2 ;
        RECT 136.600 0.000 137.000 0.400 ;
    END
  END S4BEG[8]
  PIN S4BEG[9]
    DIRECTION OUTPUT ;
    USE SIGNAL ;
    ANTENNADIFFAREA 2.724000 ;
    PORT
      LAYER Metal2 ;
        RECT 137.560 0.000 137.960 0.400 ;
    END
  END S4BEG[9]
  PIN S4END[0]
    DIRECTION INPUT ;
    USE SIGNAL ;
    ANTENNAGATEAREA 1.046500 ;
    PORT
      LAYER Metal2 ;
        RECT 128.920 214.640 129.320 215.040 ;
    END
  END S4END[0]
  PIN S4END[10]
    DIRECTION INPUT ;
    USE SIGNAL ;
    ANTENNAGATEAREA 0.180700 ;
    PORT
      LAYER Metal2 ;
        RECT 138.520 214.640 138.920 215.040 ;
    END
  END S4END[10]
  PIN S4END[11]
    DIRECTION INPUT ;
    USE SIGNAL ;
    ANTENNAGATEAREA 0.180700 ;
    PORT
      LAYER Metal2 ;
        RECT 139.480 214.640 139.880 215.040 ;
    END
  END S4END[11]
  PIN S4END[12]
    DIRECTION INPUT ;
    USE SIGNAL ;
    ANTENNAGATEAREA 0.180700 ;
    PORT
      LAYER Metal2 ;
        RECT 140.440 214.640 140.840 215.040 ;
    END
  END S4END[12]
  PIN S4END[13]
    DIRECTION INPUT ;
    USE SIGNAL ;
    ANTENNAGATEAREA 0.180700 ;
    PORT
      LAYER Metal2 ;
        RECT 141.400 214.640 141.800 215.040 ;
    END
  END S4END[13]
  PIN S4END[14]
    DIRECTION INPUT ;
    USE SIGNAL ;
    ANTENNAGATEAREA 0.180700 ;
    PORT
      LAYER Metal2 ;
        RECT 142.360 214.640 142.760 215.040 ;
    END
  END S4END[14]
  PIN S4END[15]
    DIRECTION INPUT ;
    USE SIGNAL ;
    ANTENNAGATEAREA 0.180700 ;
    PORT
      LAYER Metal2 ;
        RECT 143.320 214.640 143.720 215.040 ;
    END
  END S4END[15]
  PIN S4END[1]
    DIRECTION INPUT ;
    USE SIGNAL ;
    ANTENNAGATEAREA 1.066000 ;
    PORT
      LAYER Metal2 ;
        RECT 129.880 214.640 130.280 215.040 ;
    END
  END S4END[1]
  PIN S4END[2]
    DIRECTION INPUT ;
    USE SIGNAL ;
    ANTENNAGATEAREA 1.136200 ;
    PORT
      LAYER Metal2 ;
        RECT 130.840 214.640 131.240 215.040 ;
    END
  END S4END[2]
  PIN S4END[3]
    DIRECTION INPUT ;
    USE SIGNAL ;
    ANTENNAGATEAREA 1.107600 ;
    PORT
      LAYER Metal2 ;
        RECT 131.800 214.640 132.200 215.040 ;
    END
  END S4END[3]
  PIN S4END[4]
    DIRECTION INPUT ;
    USE SIGNAL ;
    ANTENNAGATEAREA 0.180700 ;
    PORT
      LAYER Metal2 ;
        RECT 132.760 214.640 133.160 215.040 ;
    END
  END S4END[4]
  PIN S4END[5]
    DIRECTION INPUT ;
    USE SIGNAL ;
    ANTENNAGATEAREA 0.180700 ;
    PORT
      LAYER Metal2 ;
        RECT 133.720 214.640 134.120 215.040 ;
    END
  END S4END[5]
  PIN S4END[6]
    DIRECTION INPUT ;
    USE SIGNAL ;
    ANTENNAGATEAREA 0.180700 ;
    PORT
      LAYER Metal2 ;
        RECT 134.680 214.640 135.080 215.040 ;
    END
  END S4END[6]
  PIN S4END[7]
    DIRECTION INPUT ;
    USE SIGNAL ;
    ANTENNAGATEAREA 0.180700 ;
    PORT
      LAYER Metal2 ;
        RECT 135.640 214.640 136.040 215.040 ;
    END
  END S4END[7]
  PIN S4END[8]
    DIRECTION INPUT ;
    USE SIGNAL ;
    ANTENNAGATEAREA 0.180700 ;
    PORT
      LAYER Metal2 ;
        RECT 136.600 214.640 137.000 215.040 ;
    END
  END S4END[8]
  PIN S4END[9]
    DIRECTION INPUT ;
    USE SIGNAL ;
    ANTENNAGATEAREA 0.180700 ;
    PORT
      LAYER Metal2 ;
        RECT 137.560 214.640 137.960 215.040 ;
    END
  END S4END[9]
  PIN SS4BEG[0]
    DIRECTION OUTPUT ;
    USE SIGNAL ;
    ANTENNADIFFAREA 2.724000 ;
    PORT
      LAYER Metal2 ;
        RECT 156.760 0.000 157.160 0.400 ;
    END
  END SS4BEG[0]
  PIN SS4BEG[10]
    DIRECTION OUTPUT ;
    USE SIGNAL ;
    ANTENNADIFFAREA 2.724000 ;
    PORT
      LAYER Metal2 ;
        RECT 166.360 0.000 166.760 0.400 ;
    END
  END SS4BEG[10]
  PIN SS4BEG[11]
    DIRECTION OUTPUT ;
    USE SIGNAL ;
    ANTENNADIFFAREA 2.724000 ;
    PORT
      LAYER Metal2 ;
        RECT 167.320 0.000 167.720 0.400 ;
    END
  END SS4BEG[11]
  PIN SS4BEG[12]
    DIRECTION OUTPUT ;
    USE SIGNAL ;
    ANTENNADIFFAREA 2.724000 ;
    PORT
      LAYER Metal2 ;
        RECT 168.280 0.000 168.680 0.400 ;
    END
  END SS4BEG[12]
  PIN SS4BEG[13]
    DIRECTION OUTPUT ;
    USE SIGNAL ;
    ANTENNADIFFAREA 2.724000 ;
    PORT
      LAYER Metal2 ;
        RECT 169.240 0.000 169.640 0.400 ;
    END
  END SS4BEG[13]
  PIN SS4BEG[14]
    DIRECTION OUTPUT ;
    USE SIGNAL ;
    ANTENNADIFFAREA 2.724000 ;
    PORT
      LAYER Metal2 ;
        RECT 170.200 0.000 170.600 0.400 ;
    END
  END SS4BEG[14]
  PIN SS4BEG[15]
    DIRECTION OUTPUT ;
    USE SIGNAL ;
    ANTENNADIFFAREA 2.724000 ;
    PORT
      LAYER Metal2 ;
        RECT 171.160 0.000 171.560 0.400 ;
    END
  END SS4BEG[15]
  PIN SS4BEG[1]
    DIRECTION OUTPUT ;
    USE SIGNAL ;
    ANTENNADIFFAREA 2.724000 ;
    PORT
      LAYER Metal2 ;
        RECT 157.720 0.000 158.120 0.400 ;
    END
  END SS4BEG[1]
  PIN SS4BEG[2]
    DIRECTION OUTPUT ;
    USE SIGNAL ;
    ANTENNADIFFAREA 2.724000 ;
    PORT
      LAYER Metal2 ;
        RECT 158.680 0.000 159.080 0.400 ;
    END
  END SS4BEG[2]
  PIN SS4BEG[3]
    DIRECTION OUTPUT ;
    USE SIGNAL ;
    ANTENNADIFFAREA 2.724000 ;
    PORT
      LAYER Metal2 ;
        RECT 159.640 0.000 160.040 0.400 ;
    END
  END SS4BEG[3]
  PIN SS4BEG[4]
    DIRECTION OUTPUT ;
    USE SIGNAL ;
    ANTENNADIFFAREA 2.724000 ;
    PORT
      LAYER Metal2 ;
        RECT 160.600 0.000 161.000 0.400 ;
    END
  END SS4BEG[4]
  PIN SS4BEG[5]
    DIRECTION OUTPUT ;
    USE SIGNAL ;
    ANTENNADIFFAREA 2.724000 ;
    PORT
      LAYER Metal2 ;
        RECT 161.560 0.000 161.960 0.400 ;
    END
  END SS4BEG[5]
  PIN SS4BEG[6]
    DIRECTION OUTPUT ;
    USE SIGNAL ;
    ANTENNADIFFAREA 2.724000 ;
    PORT
      LAYER Metal2 ;
        RECT 162.520 0.000 162.920 0.400 ;
    END
  END SS4BEG[6]
  PIN SS4BEG[7]
    DIRECTION OUTPUT ;
    USE SIGNAL ;
    ANTENNADIFFAREA 2.724000 ;
    PORT
      LAYER Metal2 ;
        RECT 163.480 0.000 163.880 0.400 ;
    END
  END SS4BEG[7]
  PIN SS4BEG[8]
    DIRECTION OUTPUT ;
    USE SIGNAL ;
    ANTENNADIFFAREA 2.724000 ;
    PORT
      LAYER Metal2 ;
        RECT 164.440 0.000 164.840 0.400 ;
    END
  END SS4BEG[8]
  PIN SS4BEG[9]
    DIRECTION OUTPUT ;
    USE SIGNAL ;
    ANTENNADIFFAREA 2.724000 ;
    PORT
      LAYER Metal2 ;
        RECT 165.400 0.000 165.800 0.400 ;
    END
  END SS4BEG[9]
  PIN SS4END[0]
    DIRECTION INPUT ;
    USE SIGNAL ;
    ANTENNAGATEAREA 0.681200 ;
    PORT
      LAYER Metal2 ;
        RECT 156.760 214.640 157.160 215.040 ;
    END
  END SS4END[0]
  PIN SS4END[10]
    DIRECTION INPUT ;
    USE SIGNAL ;
    ANTENNAGATEAREA 0.180700 ;
    PORT
      LAYER Metal2 ;
        RECT 166.360 214.640 166.760 215.040 ;
    END
  END SS4END[10]
  PIN SS4END[11]
    DIRECTION INPUT ;
    USE SIGNAL ;
    ANTENNAGATEAREA 0.180700 ;
    PORT
      LAYER Metal2 ;
        RECT 167.320 214.640 167.720 215.040 ;
    END
  END SS4END[11]
  PIN SS4END[12]
    DIRECTION INPUT ;
    USE SIGNAL ;
    ANTENNAGATEAREA 0.180700 ;
    PORT
      LAYER Metal2 ;
        RECT 168.280 214.640 168.680 215.040 ;
    END
  END SS4END[12]
  PIN SS4END[13]
    DIRECTION INPUT ;
    USE SIGNAL ;
    ANTENNAGATEAREA 0.180700 ;
    PORT
      LAYER Metal2 ;
        RECT 169.240 214.640 169.640 215.040 ;
    END
  END SS4END[13]
  PIN SS4END[14]
    DIRECTION INPUT ;
    USE SIGNAL ;
    ANTENNAGATEAREA 0.180700 ;
    PORT
      LAYER Metal2 ;
        RECT 170.200 214.640 170.600 215.040 ;
    END
  END SS4END[14]
  PIN SS4END[15]
    DIRECTION INPUT ;
    USE SIGNAL ;
    ANTENNAGATEAREA 0.180700 ;
    PORT
      LAYER Metal2 ;
        RECT 171.160 214.640 171.560 215.040 ;
    END
  END SS4END[15]
  PIN SS4END[1]
    DIRECTION INPUT ;
    USE SIGNAL ;
    ANTENNAGATEAREA 0.639600 ;
    PORT
      LAYER Metal2 ;
        RECT 157.720 214.640 158.120 215.040 ;
    END
  END SS4END[1]
  PIN SS4END[2]
    DIRECTION INPUT ;
    USE SIGNAL ;
    ANTENNAGATEAREA 0.618800 ;
    PORT
      LAYER Metal2 ;
        RECT 158.680 214.640 159.080 215.040 ;
    END
  END SS4END[2]
  PIN SS4END[3]
    DIRECTION INPUT ;
    USE SIGNAL ;
    ANTENNAGATEAREA 0.647400 ;
    PORT
      LAYER Metal2 ;
        RECT 159.640 214.640 160.040 215.040 ;
    END
  END SS4END[3]
  PIN SS4END[4]
    DIRECTION INPUT ;
    USE SIGNAL ;
    ANTENNAGATEAREA 0.180700 ;
    PORT
      LAYER Metal2 ;
        RECT 160.600 214.640 161.000 215.040 ;
    END
  END SS4END[4]
  PIN SS4END[5]
    DIRECTION INPUT ;
    USE SIGNAL ;
    ANTENNAGATEAREA 0.180700 ;
    PORT
      LAYER Metal2 ;
        RECT 161.560 214.640 161.960 215.040 ;
    END
  END SS4END[5]
  PIN SS4END[6]
    DIRECTION INPUT ;
    USE SIGNAL ;
    ANTENNAGATEAREA 0.180700 ;
    PORT
      LAYER Metal2 ;
        RECT 162.520 214.640 162.920 215.040 ;
    END
  END SS4END[6]
  PIN SS4END[7]
    DIRECTION INPUT ;
    USE SIGNAL ;
    ANTENNAGATEAREA 0.180700 ;
    PORT
      LAYER Metal2 ;
        RECT 163.480 214.640 163.880 215.040 ;
    END
  END SS4END[7]
  PIN SS4END[8]
    DIRECTION INPUT ;
    USE SIGNAL ;
    ANTENNAGATEAREA 0.180700 ;
    PORT
      LAYER Metal2 ;
        RECT 164.440 214.640 164.840 215.040 ;
    END
  END SS4END[8]
  PIN SS4END[9]
    DIRECTION INPUT ;
    USE SIGNAL ;
    ANTENNAGATEAREA 0.180700 ;
    PORT
      LAYER Metal2 ;
        RECT 165.400 214.640 165.800 215.040 ;
    END
  END SS4END[9]
  PIN UserCLK
    DIRECTION INPUT ;
    USE SIGNAL ;
    ANTENNAGATEAREA 1.450800 ;
    PORT
      LAYER Metal3 ;
        RECT 0.000 160.660 0.400 161.060 ;
    END
  END UserCLK
  PIN UserCLKo
    DIRECTION OUTPUT ;
    USE SIGNAL ;
    ANTENNADIFFAREA 2.724000 ;
    PORT
      LAYER Metal3 ;
        RECT 214.640 160.660 215.040 161.060 ;
    END
  END UserCLKo
  PIN VGND
    DIRECTION INOUT ;
    USE GROUND ;
    PORT
      LAYER Metal4 ;
        RECT 21.580 0.000 23.780 215.040 ;
    END
    PORT
      LAYER Metal4 ;
        RECT 97.180 0.000 99.380 215.040 ;
    END
    PORT
      LAYER Metal4 ;
        RECT 172.780 0.000 174.980 215.040 ;
    END
  END VGND
  PIN VPWR
    DIRECTION INOUT ;
    USE POWER ;
    PORT
      LAYER Metal4 ;
        RECT 15.380 0.000 17.580 215.040 ;
    END
    PORT
      LAYER Metal4 ;
        RECT 90.980 0.000 93.180 215.040 ;
    END
    PORT
      LAYER Metal4 ;
        RECT 166.580 0.000 168.780 215.040 ;
    END
  END VPWR
  PIN W1BEG[0]
    DIRECTION OUTPUT ;
    USE SIGNAL ;
    ANTENNADIFFAREA 2.724000 ;
    PORT
      LAYER Metal3 ;
        RECT 0.000 80.020 0.400 80.420 ;
    END
  END W1BEG[0]
  PIN W1BEG[1]
    DIRECTION OUTPUT ;
    USE SIGNAL ;
    ANTENNADIFFAREA 2.724000 ;
    PORT
      LAYER Metal3 ;
        RECT 0.000 81.700 0.400 82.100 ;
    END
  END W1BEG[1]
  PIN W1BEG[2]
    DIRECTION OUTPUT ;
    USE SIGNAL ;
    ANTENNADIFFAREA 2.724000 ;
    PORT
      LAYER Metal3 ;
        RECT 0.000 83.380 0.400 83.780 ;
    END
  END W1BEG[2]
  PIN W1BEG[3]
    DIRECTION OUTPUT ;
    USE SIGNAL ;
    ANTENNADIFFAREA 2.724000 ;
    PORT
      LAYER Metal3 ;
        RECT 0.000 85.060 0.400 85.460 ;
    END
  END W1BEG[3]
  PIN W1END[0]
    DIRECTION INPUT ;
    USE SIGNAL ;
    ANTENNAGATEAREA 0.696800 ;
    ANTENNADIFFAREA 18.138599 ;
    PORT
      LAYER Metal3 ;
        RECT 214.640 80.020 215.040 80.420 ;
    END
  END W1END[0]
  PIN W1END[1]
    DIRECTION INPUT ;
    USE SIGNAL ;
    ANTENNAGATEAREA 1.775800 ;
    PORT
      LAYER Metal3 ;
        RECT 214.640 81.700 215.040 82.100 ;
    END
  END W1END[1]
  PIN W1END[2]
    DIRECTION INPUT ;
    USE SIGNAL ;
    ANTENNAGATEAREA 2.334800 ;
    PORT
      LAYER Metal3 ;
        RECT 214.640 83.380 215.040 83.780 ;
    END
  END W1END[2]
  PIN W1END[3]
    DIRECTION INPUT ;
    USE SIGNAL ;
    ANTENNAGATEAREA 2.411500 ;
    PORT
      LAYER Metal3 ;
        RECT 214.640 85.060 215.040 85.460 ;
    END
  END W1END[3]
  PIN W2BEG[0]
    DIRECTION OUTPUT ;
    USE SIGNAL ;
    ANTENNADIFFAREA 2.724000 ;
    PORT
      LAYER Metal3 ;
        RECT 0.000 86.740 0.400 87.140 ;
    END
  END W2BEG[0]
  PIN W2BEG[1]
    DIRECTION OUTPUT ;
    USE SIGNAL ;
    ANTENNADIFFAREA 2.724000 ;
    PORT
      LAYER Metal3 ;
        RECT 0.000 88.420 0.400 88.820 ;
    END
  END W2BEG[1]
  PIN W2BEG[2]
    DIRECTION OUTPUT ;
    USE SIGNAL ;
    ANTENNADIFFAREA 2.724000 ;
    PORT
      LAYER Metal3 ;
        RECT 0.000 90.100 0.400 90.500 ;
    END
  END W2BEG[2]
  PIN W2BEG[3]
    DIRECTION OUTPUT ;
    USE SIGNAL ;
    ANTENNADIFFAREA 2.724000 ;
    PORT
      LAYER Metal3 ;
        RECT 0.000 91.780 0.400 92.180 ;
    END
  END W2BEG[3]
  PIN W2BEG[4]
    DIRECTION OUTPUT ;
    USE SIGNAL ;
    ANTENNADIFFAREA 2.724000 ;
    PORT
      LAYER Metal3 ;
        RECT 0.000 93.460 0.400 93.860 ;
    END
  END W2BEG[4]
  PIN W2BEG[5]
    DIRECTION OUTPUT ;
    USE SIGNAL ;
    ANTENNADIFFAREA 2.724000 ;
    PORT
      LAYER Metal3 ;
        RECT 0.000 95.140 0.400 95.540 ;
    END
  END W2BEG[5]
  PIN W2BEG[6]
    DIRECTION OUTPUT ;
    USE SIGNAL ;
    ANTENNADIFFAREA 2.724000 ;
    PORT
      LAYER Metal3 ;
        RECT 0.000 96.820 0.400 97.220 ;
    END
  END W2BEG[6]
  PIN W2BEG[7]
    DIRECTION OUTPUT ;
    USE SIGNAL ;
    ANTENNADIFFAREA 2.724000 ;
    PORT
      LAYER Metal3 ;
        RECT 0.000 98.500 0.400 98.900 ;
    END
  END W2BEG[7]
  PIN W2BEGb[0]
    DIRECTION OUTPUT ;
    USE SIGNAL ;
    ANTENNADIFFAREA 2.724000 ;
    PORT
      LAYER Metal3 ;
        RECT 0.000 100.180 0.400 100.580 ;
    END
  END W2BEGb[0]
  PIN W2BEGb[1]
    DIRECTION OUTPUT ;
    USE SIGNAL ;
    ANTENNADIFFAREA 2.724000 ;
    PORT
      LAYER Metal3 ;
        RECT 0.000 101.860 0.400 102.260 ;
    END
  END W2BEGb[1]
  PIN W2BEGb[2]
    DIRECTION OUTPUT ;
    USE SIGNAL ;
    ANTENNADIFFAREA 2.724000 ;
    PORT
      LAYER Metal3 ;
        RECT 0.000 103.540 0.400 103.940 ;
    END
  END W2BEGb[2]
  PIN W2BEGb[3]
    DIRECTION OUTPUT ;
    USE SIGNAL ;
    ANTENNADIFFAREA 2.724000 ;
    PORT
      LAYER Metal3 ;
        RECT 0.000 105.220 0.400 105.620 ;
    END
  END W2BEGb[3]
  PIN W2BEGb[4]
    DIRECTION OUTPUT ;
    USE SIGNAL ;
    ANTENNADIFFAREA 2.724000 ;
    PORT
      LAYER Metal3 ;
        RECT 0.000 106.900 0.400 107.300 ;
    END
  END W2BEGb[4]
  PIN W2BEGb[5]
    DIRECTION OUTPUT ;
    USE SIGNAL ;
    ANTENNADIFFAREA 2.724000 ;
    PORT
      LAYER Metal3 ;
        RECT 0.000 108.580 0.400 108.980 ;
    END
  END W2BEGb[5]
  PIN W2BEGb[6]
    DIRECTION OUTPUT ;
    USE SIGNAL ;
    ANTENNADIFFAREA 2.724000 ;
    PORT
      LAYER Metal3 ;
        RECT 0.000 110.260 0.400 110.660 ;
    END
  END W2BEGb[6]
  PIN W2BEGb[7]
    DIRECTION OUTPUT ;
    USE SIGNAL ;
    ANTENNADIFFAREA 2.724000 ;
    PORT
      LAYER Metal3 ;
        RECT 0.000 111.940 0.400 112.340 ;
    END
  END W2BEGb[7]
  PIN W2END[0]
    DIRECTION INPUT ;
    USE SIGNAL ;
    ANTENNAGATEAREA 0.455000 ;
    PORT
      LAYER Metal3 ;
        RECT 214.640 100.180 215.040 100.580 ;
    END
  END W2END[0]
  PIN W2END[1]
    DIRECTION INPUT ;
    USE SIGNAL ;
    ANTENNAGATEAREA 1.359800 ;
    PORT
      LAYER Metal3 ;
        RECT 214.640 101.860 215.040 102.260 ;
    END
  END W2END[1]
  PIN W2END[2]
    DIRECTION INPUT ;
    USE SIGNAL ;
    ANTENNAGATEAREA 1.443800 ;
    PORT
      LAYER Metal3 ;
        RECT 214.640 103.540 215.040 103.940 ;
    END
  END W2END[2]
  PIN W2END[3]
    DIRECTION INPUT ;
    USE SIGNAL ;
    ANTENNAGATEAREA 1.406900 ;
    PORT
      LAYER Metal3 ;
        RECT 214.640 105.220 215.040 105.620 ;
    END
  END W2END[3]
  PIN W2END[4]
    DIRECTION INPUT ;
    USE SIGNAL ;
    ANTENNAGATEAREA 1.547000 ;
    PORT
      LAYER Metal3 ;
        RECT 214.640 106.900 215.040 107.300 ;
    END
  END W2END[4]
  PIN W2END[5]
    DIRECTION INPUT ;
    USE SIGNAL ;
    ANTENNAGATEAREA 0.426400 ;
    ANTENNADIFFAREA 8.061600 ;
    PORT
      LAYER Metal3 ;
        RECT 214.640 108.580 215.040 108.980 ;
    END
  END W2END[5]
  PIN W2END[6]
    DIRECTION INPUT ;
    USE SIGNAL ;
    ANTENNAGATEAREA 0.426400 ;
    PORT
      LAYER Metal3 ;
        RECT 214.640 110.260 215.040 110.660 ;
    END
  END W2END[6]
  PIN W2END[7]
    DIRECTION INPUT ;
    USE SIGNAL ;
    ANTENNAGATEAREA 0.668200 ;
    PORT
      LAYER Metal3 ;
        RECT 214.640 111.940 215.040 112.340 ;
    END
  END W2END[7]
  PIN W2MID[0]
    DIRECTION INPUT ;
    USE SIGNAL ;
    ANTENNAGATEAREA 0.787800 ;
    PORT
      LAYER Metal3 ;
        RECT 214.640 86.740 215.040 87.140 ;
    END
  END W2MID[0]
  PIN W2MID[1]
    DIRECTION INPUT ;
    USE SIGNAL ;
    ANTENNAGATEAREA 1.033500 ;
    PORT
      LAYER Metal3 ;
        RECT 214.640 88.420 215.040 88.820 ;
    END
  END W2MID[1]
  PIN W2MID[2]
    DIRECTION INPUT ;
    USE SIGNAL ;
    ANTENNAGATEAREA 0.848900 ;
    PORT
      LAYER Metal3 ;
        RECT 214.640 90.100 215.040 90.500 ;
    END
  END W2MID[2]
  PIN W2MID[3]
    DIRECTION INPUT ;
    USE SIGNAL ;
    ANTENNAGATEAREA 1.033500 ;
    ANTENNADIFFAREA 50.384998 ;
    PORT
      LAYER Metal3 ;
        RECT 214.640 91.780 215.040 92.180 ;
    END
  END W2MID[3]
  PIN W2MID[4]
    DIRECTION INPUT ;
    USE SIGNAL ;
    ANTENNAGATEAREA 0.820300 ;
    ANTENNADIFFAREA 8.061600 ;
    PORT
      LAYER Metal3 ;
        RECT 214.640 93.460 215.040 93.860 ;
    END
  END W2MID[4]
  PIN W2MID[5]
    DIRECTION INPUT ;
    USE SIGNAL ;
    ANTENNAGATEAREA 1.033500 ;
    PORT
      LAYER Metal3 ;
        RECT 214.640 95.140 215.040 95.540 ;
    END
  END W2MID[5]
  PIN W2MID[6]
    DIRECTION INPUT ;
    USE SIGNAL ;
    ANTENNAGATEAREA 0.820300 ;
    PORT
      LAYER Metal3 ;
        RECT 214.640 96.820 215.040 97.220 ;
    END
  END W2MID[6]
  PIN W2MID[7]
    DIRECTION INPUT ;
    USE SIGNAL ;
    ANTENNAGATEAREA 1.033500 ;
    PORT
      LAYER Metal3 ;
        RECT 214.640 98.500 215.040 98.900 ;
    END
  END W2MID[7]
  PIN W6BEG[0]
    DIRECTION OUTPUT ;
    USE SIGNAL ;
    ANTENNADIFFAREA 2.724000 ;
    PORT
      LAYER Metal3 ;
        RECT 0.000 140.500 0.400 140.900 ;
    END
  END W6BEG[0]
  PIN W6BEG[10]
    DIRECTION OUTPUT ;
    USE SIGNAL ;
    ANTENNADIFFAREA 2.724000 ;
    PORT
      LAYER Metal3 ;
        RECT 0.000 157.300 0.400 157.700 ;
    END
  END W6BEG[10]
  PIN W6BEG[11]
    DIRECTION OUTPUT ;
    USE SIGNAL ;
    ANTENNADIFFAREA 2.724000 ;
    PORT
      LAYER Metal3 ;
        RECT 0.000 158.980 0.400 159.380 ;
    END
  END W6BEG[11]
  PIN W6BEG[1]
    DIRECTION OUTPUT ;
    USE SIGNAL ;
    ANTENNADIFFAREA 2.724000 ;
    PORT
      LAYER Metal3 ;
        RECT 0.000 142.180 0.400 142.580 ;
    END
  END W6BEG[1]
  PIN W6BEG[2]
    DIRECTION OUTPUT ;
    USE SIGNAL ;
    ANTENNADIFFAREA 2.724000 ;
    PORT
      LAYER Metal3 ;
        RECT 0.000 143.860 0.400 144.260 ;
    END
  END W6BEG[2]
  PIN W6BEG[3]
    DIRECTION OUTPUT ;
    USE SIGNAL ;
    ANTENNADIFFAREA 2.724000 ;
    PORT
      LAYER Metal3 ;
        RECT 0.000 145.540 0.400 145.940 ;
    END
  END W6BEG[3]
  PIN W6BEG[4]
    DIRECTION OUTPUT ;
    USE SIGNAL ;
    ANTENNADIFFAREA 2.724000 ;
    PORT
      LAYER Metal3 ;
        RECT 0.000 147.220 0.400 147.620 ;
    END
  END W6BEG[4]
  PIN W6BEG[5]
    DIRECTION OUTPUT ;
    USE SIGNAL ;
    ANTENNADIFFAREA 2.724000 ;
    PORT
      LAYER Metal3 ;
        RECT 0.000 148.900 0.400 149.300 ;
    END
  END W6BEG[5]
  PIN W6BEG[6]
    DIRECTION OUTPUT ;
    USE SIGNAL ;
    ANTENNADIFFAREA 2.724000 ;
    PORT
      LAYER Metal3 ;
        RECT 0.000 150.580 0.400 150.980 ;
    END
  END W6BEG[6]
  PIN W6BEG[7]
    DIRECTION OUTPUT ;
    USE SIGNAL ;
    ANTENNADIFFAREA 2.724000 ;
    PORT
      LAYER Metal3 ;
        RECT 0.000 152.260 0.400 152.660 ;
    END
  END W6BEG[7]
  PIN W6BEG[8]
    DIRECTION OUTPUT ;
    USE SIGNAL ;
    ANTENNADIFFAREA 2.724000 ;
    PORT
      LAYER Metal3 ;
        RECT 0.000 153.940 0.400 154.340 ;
    END
  END W6BEG[8]
  PIN W6BEG[9]
    DIRECTION OUTPUT ;
    USE SIGNAL ;
    ANTENNADIFFAREA 2.724000 ;
    PORT
      LAYER Metal3 ;
        RECT 0.000 155.620 0.400 156.020 ;
    END
  END W6BEG[9]
  PIN W6END[0]
    DIRECTION INPUT ;
    USE SIGNAL ;
    ANTENNAGATEAREA 1.526200 ;
    PORT
      LAYER Metal3 ;
        RECT 214.640 140.500 215.040 140.900 ;
    END
  END W6END[0]
  PIN W6END[10]
    DIRECTION INPUT ;
    USE SIGNAL ;
    ANTENNAGATEAREA 0.180700 ;
    PORT
      LAYER Metal3 ;
        RECT 214.640 157.300 215.040 157.700 ;
    END
  END W6END[10]
  PIN W6END[11]
    DIRECTION INPUT ;
    USE SIGNAL ;
    ANTENNAGATEAREA 0.180700 ;
    PORT
      LAYER Metal3 ;
        RECT 214.640 158.980 215.040 159.380 ;
    END
  END W6END[11]
  PIN W6END[1]
    DIRECTION INPUT ;
    USE SIGNAL ;
    ANTENNAGATEAREA 2.206100 ;
    PORT
      LAYER Metal3 ;
        RECT 214.640 142.180 215.040 142.580 ;
    END
  END W6END[1]
  PIN W6END[2]
    DIRECTION INPUT ;
    USE SIGNAL ;
    ANTENNAGATEAREA 0.180700 ;
    PORT
      LAYER Metal3 ;
        RECT 214.640 143.860 215.040 144.260 ;
    END
  END W6END[2]
  PIN W6END[3]
    DIRECTION INPUT ;
    USE SIGNAL ;
    ANTENNAGATEAREA 0.180700 ;
    PORT
      LAYER Metal3 ;
        RECT 214.640 145.540 215.040 145.940 ;
    END
  END W6END[3]
  PIN W6END[4]
    DIRECTION INPUT ;
    USE SIGNAL ;
    ANTENNAGATEAREA 0.180700 ;
    PORT
      LAYER Metal3 ;
        RECT 214.640 147.220 215.040 147.620 ;
    END
  END W6END[4]
  PIN W6END[5]
    DIRECTION INPUT ;
    USE SIGNAL ;
    ANTENNAGATEAREA 0.180700 ;
    PORT
      LAYER Metal3 ;
        RECT 214.640 148.900 215.040 149.300 ;
    END
  END W6END[5]
  PIN W6END[6]
    DIRECTION INPUT ;
    USE SIGNAL ;
    ANTENNAGATEAREA 0.180700 ;
    PORT
      LAYER Metal3 ;
        RECT 214.640 150.580 215.040 150.980 ;
    END
  END W6END[6]
  PIN W6END[7]
    DIRECTION INPUT ;
    USE SIGNAL ;
    ANTENNAGATEAREA 0.180700 ;
    PORT
      LAYER Metal3 ;
        RECT 214.640 152.260 215.040 152.660 ;
    END
  END W6END[7]
  PIN W6END[8]
    DIRECTION INPUT ;
    USE SIGNAL ;
    ANTENNAGATEAREA 0.180700 ;
    PORT
      LAYER Metal3 ;
        RECT 214.640 153.940 215.040 154.340 ;
    END
  END W6END[8]
  PIN W6END[9]
    DIRECTION INPUT ;
    USE SIGNAL ;
    ANTENNAGATEAREA 0.180700 ;
    PORT
      LAYER Metal3 ;
        RECT 214.640 155.620 215.040 156.020 ;
    END
  END W6END[9]
  PIN WW4BEG[0]
    DIRECTION OUTPUT ;
    USE SIGNAL ;
    ANTENNADIFFAREA 2.724000 ;
    PORT
      LAYER Metal3 ;
        RECT 0.000 113.620 0.400 114.020 ;
    END
  END WW4BEG[0]
  PIN WW4BEG[10]
    DIRECTION OUTPUT ;
    USE SIGNAL ;
    ANTENNADIFFAREA 2.724000 ;
    PORT
      LAYER Metal3 ;
        RECT 0.000 130.420 0.400 130.820 ;
    END
  END WW4BEG[10]
  PIN WW4BEG[11]
    DIRECTION OUTPUT ;
    USE SIGNAL ;
    ANTENNADIFFAREA 2.724000 ;
    PORT
      LAYER Metal3 ;
        RECT 0.000 132.100 0.400 132.500 ;
    END
  END WW4BEG[11]
  PIN WW4BEG[12]
    DIRECTION OUTPUT ;
    USE SIGNAL ;
    ANTENNADIFFAREA 2.724000 ;
    PORT
      LAYER Metal3 ;
        RECT 0.000 133.780 0.400 134.180 ;
    END
  END WW4BEG[12]
  PIN WW4BEG[13]
    DIRECTION OUTPUT ;
    USE SIGNAL ;
    ANTENNADIFFAREA 2.724000 ;
    PORT
      LAYER Metal3 ;
        RECT 0.000 135.460 0.400 135.860 ;
    END
  END WW4BEG[13]
  PIN WW4BEG[14]
    DIRECTION OUTPUT ;
    USE SIGNAL ;
    ANTENNADIFFAREA 2.724000 ;
    PORT
      LAYER Metal3 ;
        RECT 0.000 137.140 0.400 137.540 ;
    END
  END WW4BEG[14]
  PIN WW4BEG[15]
    DIRECTION OUTPUT ;
    USE SIGNAL ;
    ANTENNADIFFAREA 2.724000 ;
    PORT
      LAYER Metal3 ;
        RECT 0.000 138.820 0.400 139.220 ;
    END
  END WW4BEG[15]
  PIN WW4BEG[1]
    DIRECTION OUTPUT ;
    USE SIGNAL ;
    ANTENNADIFFAREA 2.724000 ;
    PORT
      LAYER Metal3 ;
        RECT 0.000 115.300 0.400 115.700 ;
    END
  END WW4BEG[1]
  PIN WW4BEG[2]
    DIRECTION OUTPUT ;
    USE SIGNAL ;
    ANTENNADIFFAREA 2.724000 ;
    PORT
      LAYER Metal3 ;
        RECT 0.000 116.980 0.400 117.380 ;
    END
  END WW4BEG[2]
  PIN WW4BEG[3]
    DIRECTION OUTPUT ;
    USE SIGNAL ;
    ANTENNADIFFAREA 2.724000 ;
    PORT
      LAYER Metal3 ;
        RECT 0.000 118.660 0.400 119.060 ;
    END
  END WW4BEG[3]
  PIN WW4BEG[4]
    DIRECTION OUTPUT ;
    USE SIGNAL ;
    ANTENNADIFFAREA 2.724000 ;
    PORT
      LAYER Metal3 ;
        RECT 0.000 120.340 0.400 120.740 ;
    END
  END WW4BEG[4]
  PIN WW4BEG[5]
    DIRECTION OUTPUT ;
    USE SIGNAL ;
    ANTENNADIFFAREA 2.724000 ;
    PORT
      LAYER Metal3 ;
        RECT 0.000 122.020 0.400 122.420 ;
    END
  END WW4BEG[5]
  PIN WW4BEG[6]
    DIRECTION OUTPUT ;
    USE SIGNAL ;
    ANTENNADIFFAREA 2.724000 ;
    PORT
      LAYER Metal3 ;
        RECT 0.000 123.700 0.400 124.100 ;
    END
  END WW4BEG[6]
  PIN WW4BEG[7]
    DIRECTION OUTPUT ;
    USE SIGNAL ;
    ANTENNADIFFAREA 2.724000 ;
    PORT
      LAYER Metal3 ;
        RECT 0.000 125.380 0.400 125.780 ;
    END
  END WW4BEG[7]
  PIN WW4BEG[8]
    DIRECTION OUTPUT ;
    USE SIGNAL ;
    ANTENNADIFFAREA 2.724000 ;
    PORT
      LAYER Metal3 ;
        RECT 0.000 127.060 0.400 127.460 ;
    END
  END WW4BEG[8]
  PIN WW4BEG[9]
    DIRECTION OUTPUT ;
    USE SIGNAL ;
    ANTENNADIFFAREA 2.724000 ;
    PORT
      LAYER Metal3 ;
        RECT 0.000 128.740 0.400 129.140 ;
    END
  END WW4BEG[9]
  PIN WW4END[0]
    DIRECTION INPUT ;
    USE SIGNAL ;
    ANTENNAGATEAREA 0.652600 ;
    PORT
      LAYER Metal3 ;
        RECT 214.640 113.620 215.040 114.020 ;
    END
  END WW4END[0]
  PIN WW4END[10]
    DIRECTION INPUT ;
    USE SIGNAL ;
    ANTENNAGATEAREA 0.180700 ;
    PORT
      LAYER Metal3 ;
        RECT 214.640 130.420 215.040 130.820 ;
    END
  END WW4END[10]
  PIN WW4END[11]
    DIRECTION INPUT ;
    USE SIGNAL ;
    ANTENNAGATEAREA 0.180700 ;
    PORT
      LAYER Metal3 ;
        RECT 214.640 132.100 215.040 132.500 ;
    END
  END WW4END[11]
  PIN WW4END[12]
    DIRECTION INPUT ;
    USE SIGNAL ;
    ANTENNAGATEAREA 0.180700 ;
    PORT
      LAYER Metal3 ;
        RECT 214.640 133.780 215.040 134.180 ;
    END
  END WW4END[12]
  PIN WW4END[13]
    DIRECTION INPUT ;
    USE SIGNAL ;
    ANTENNAGATEAREA 0.180700 ;
    PORT
      LAYER Metal3 ;
        RECT 214.640 135.460 215.040 135.860 ;
    END
  END WW4END[13]
  PIN WW4END[14]
    DIRECTION INPUT ;
    USE SIGNAL ;
    ANTENNAGATEAREA 0.180700 ;
    PORT
      LAYER Metal3 ;
        RECT 214.640 137.140 215.040 137.540 ;
    END
  END WW4END[14]
  PIN WW4END[15]
    DIRECTION INPUT ;
    USE SIGNAL ;
    ANTENNAGATEAREA 0.180700 ;
    PORT
      LAYER Metal3 ;
        RECT 214.640 138.820 215.040 139.220 ;
    END
  END WW4END[15]
  PIN WW4END[1]
    DIRECTION INPUT ;
    USE SIGNAL ;
    ANTENNAGATEAREA 0.455000 ;
    PORT
      LAYER Metal3 ;
        RECT 214.640 115.300 215.040 115.700 ;
    END
  END WW4END[1]
  PIN WW4END[2]
    DIRECTION INPUT ;
    USE SIGNAL ;
    ANTENNAGATEAREA 0.800800 ;
    PORT
      LAYER Metal3 ;
        RECT 214.640 116.980 215.040 117.380 ;
    END
  END WW4END[2]
  PIN WW4END[3]
    DIRECTION INPUT ;
    USE SIGNAL ;
    ANTENNAGATEAREA 0.652600 ;
    ANTENNADIFFAREA 6.046200 ;
    PORT
      LAYER Metal3 ;
        RECT 214.640 118.660 215.040 119.060 ;
    END
  END WW4END[3]
  PIN WW4END[4]
    DIRECTION INPUT ;
    USE SIGNAL ;
    ANTENNAGATEAREA 0.180700 ;
    PORT
      LAYER Metal3 ;
        RECT 214.640 120.340 215.040 120.740 ;
    END
  END WW4END[4]
  PIN WW4END[5]
    DIRECTION INPUT ;
    USE SIGNAL ;
    ANTENNAGATEAREA 0.180700 ;
    PORT
      LAYER Metal3 ;
        RECT 214.640 122.020 215.040 122.420 ;
    END
  END WW4END[5]
  PIN WW4END[6]
    DIRECTION INPUT ;
    USE SIGNAL ;
    ANTENNAGATEAREA 0.180700 ;
    PORT
      LAYER Metal3 ;
        RECT 214.640 123.700 215.040 124.100 ;
    END
  END WW4END[6]
  PIN WW4END[7]
    DIRECTION INPUT ;
    USE SIGNAL ;
    ANTENNAGATEAREA 0.180700 ;
    PORT
      LAYER Metal3 ;
        RECT 214.640 125.380 215.040 125.780 ;
    END
  END WW4END[7]
  PIN WW4END[8]
    DIRECTION INPUT ;
    USE SIGNAL ;
    ANTENNAGATEAREA 0.180700 ;
    PORT
      LAYER Metal3 ;
        RECT 214.640 127.060 215.040 127.460 ;
    END
  END WW4END[8]
  PIN WW4END[9]
    DIRECTION INPUT ;
    USE SIGNAL ;
    ANTENNAGATEAREA 0.180700 ;
    PORT
      LAYER Metal3 ;
        RECT 214.640 128.740 215.040 129.140 ;
    END
  END WW4END[9]
  OBS
      LAYER GatPoly ;
        RECT 2.880 3.630 212.160 208.050 ;
      LAYER Metal1 ;
        RECT 2.880 3.560 212.160 208.120 ;
      LAYER Metal2 ;
        RECT 0.375 214.430 1.990 214.765 ;
        RECT 2.810 214.430 2.950 214.765 ;
        RECT 3.770 214.430 3.910 214.765 ;
        RECT 4.730 214.430 4.870 214.765 ;
        RECT 5.690 214.430 10.630 214.765 ;
        RECT 11.450 214.430 11.590 214.765 ;
        RECT 12.410 214.430 12.550 214.765 ;
        RECT 13.370 214.430 13.510 214.765 ;
        RECT 14.330 214.430 14.470 214.765 ;
        RECT 15.290 214.430 15.430 214.765 ;
        RECT 16.250 214.430 16.390 214.765 ;
        RECT 17.210 214.430 17.350 214.765 ;
        RECT 18.170 214.430 24.070 214.765 ;
        RECT 24.890 214.430 25.030 214.765 ;
        RECT 25.850 214.430 25.990 214.765 ;
        RECT 26.810 214.430 26.950 214.765 ;
        RECT 27.770 214.430 27.910 214.765 ;
        RECT 28.730 214.430 28.870 214.765 ;
        RECT 29.690 214.430 29.830 214.765 ;
        RECT 30.650 214.430 30.790 214.765 ;
        RECT 31.610 214.430 40.390 214.765 ;
        RECT 41.210 214.430 41.350 214.765 ;
        RECT 42.170 214.430 42.310 214.765 ;
        RECT 43.130 214.430 43.270 214.765 ;
        RECT 44.090 214.430 44.230 214.765 ;
        RECT 45.050 214.430 45.190 214.765 ;
        RECT 46.010 214.430 46.150 214.765 ;
        RECT 46.970 214.430 47.110 214.765 ;
        RECT 47.930 214.430 48.070 214.765 ;
        RECT 48.890 214.430 49.030 214.765 ;
        RECT 49.850 214.430 49.990 214.765 ;
        RECT 50.810 214.430 50.950 214.765 ;
        RECT 51.770 214.430 51.910 214.765 ;
        RECT 52.730 214.430 52.870 214.765 ;
        RECT 53.690 214.430 53.830 214.765 ;
        RECT 54.650 214.430 54.790 214.765 ;
        RECT 55.610 214.430 68.230 214.765 ;
        RECT 69.050 214.430 69.190 214.765 ;
        RECT 70.010 214.430 70.150 214.765 ;
        RECT 70.970 214.430 71.110 214.765 ;
        RECT 71.930 214.430 72.070 214.765 ;
        RECT 72.890 214.430 73.030 214.765 ;
        RECT 73.850 214.430 73.990 214.765 ;
        RECT 74.810 214.430 74.950 214.765 ;
        RECT 75.770 214.430 75.910 214.765 ;
        RECT 76.730 214.430 76.870 214.765 ;
        RECT 77.690 214.430 77.830 214.765 ;
        RECT 78.650 214.430 78.790 214.765 ;
        RECT 79.610 214.430 79.750 214.765 ;
        RECT 80.570 214.430 80.710 214.765 ;
        RECT 81.530 214.430 81.670 214.765 ;
        RECT 82.490 214.430 82.630 214.765 ;
        RECT 83.450 214.430 90.310 214.765 ;
        RECT 91.130 214.430 91.270 214.765 ;
        RECT 92.090 214.430 92.230 214.765 ;
        RECT 93.050 214.430 93.190 214.765 ;
        RECT 94.010 214.430 98.950 214.765 ;
        RECT 99.770 214.430 99.910 214.765 ;
        RECT 100.730 214.430 100.870 214.765 ;
        RECT 101.690 214.430 101.830 214.765 ;
        RECT 102.650 214.430 102.790 214.765 ;
        RECT 103.610 214.430 103.750 214.765 ;
        RECT 104.570 214.430 104.710 214.765 ;
        RECT 105.530 214.430 105.670 214.765 ;
        RECT 106.490 214.430 112.390 214.765 ;
        RECT 113.210 214.430 113.350 214.765 ;
        RECT 114.170 214.430 114.310 214.765 ;
        RECT 115.130 214.430 115.270 214.765 ;
        RECT 116.090 214.430 116.230 214.765 ;
        RECT 117.050 214.430 117.190 214.765 ;
        RECT 118.010 214.430 118.150 214.765 ;
        RECT 118.970 214.430 119.110 214.765 ;
        RECT 119.930 214.430 128.710 214.765 ;
        RECT 129.530 214.430 129.670 214.765 ;
        RECT 130.490 214.430 130.630 214.765 ;
        RECT 131.450 214.430 131.590 214.765 ;
        RECT 132.410 214.430 132.550 214.765 ;
        RECT 133.370 214.430 133.510 214.765 ;
        RECT 134.330 214.430 134.470 214.765 ;
        RECT 135.290 214.430 135.430 214.765 ;
        RECT 136.250 214.430 136.390 214.765 ;
        RECT 137.210 214.430 137.350 214.765 ;
        RECT 138.170 214.430 138.310 214.765 ;
        RECT 139.130 214.430 139.270 214.765 ;
        RECT 140.090 214.430 140.230 214.765 ;
        RECT 141.050 214.430 141.190 214.765 ;
        RECT 142.010 214.430 142.150 214.765 ;
        RECT 142.970 214.430 143.110 214.765 ;
        RECT 143.930 214.430 156.550 214.765 ;
        RECT 157.370 214.430 157.510 214.765 ;
        RECT 158.330 214.430 158.470 214.765 ;
        RECT 159.290 214.430 159.430 214.765 ;
        RECT 160.250 214.430 160.390 214.765 ;
        RECT 161.210 214.430 161.350 214.765 ;
        RECT 162.170 214.430 162.310 214.765 ;
        RECT 163.130 214.430 163.270 214.765 ;
        RECT 164.090 214.430 164.230 214.765 ;
        RECT 165.050 214.430 165.190 214.765 ;
        RECT 166.010 214.430 166.150 214.765 ;
        RECT 166.970 214.430 167.110 214.765 ;
        RECT 167.930 214.430 168.070 214.765 ;
        RECT 168.890 214.430 169.030 214.765 ;
        RECT 169.850 214.430 169.990 214.765 ;
        RECT 170.810 214.430 170.950 214.765 ;
        RECT 171.770 214.430 178.630 214.765 ;
        RECT 179.450 214.430 188.230 214.765 ;
        RECT 189.050 214.430 189.190 214.765 ;
        RECT 190.010 214.430 190.150 214.765 ;
        RECT 190.970 214.430 191.110 214.765 ;
        RECT 191.930 214.430 192.070 214.765 ;
        RECT 192.890 214.430 193.030 214.765 ;
        RECT 193.850 214.430 193.990 214.765 ;
        RECT 194.810 214.430 194.950 214.765 ;
        RECT 195.770 214.430 195.910 214.765 ;
        RECT 196.730 214.430 196.870 214.765 ;
        RECT 197.690 214.430 197.830 214.765 ;
        RECT 198.650 214.430 198.790 214.765 ;
        RECT 199.610 214.430 199.750 214.765 ;
        RECT 200.570 214.430 200.710 214.765 ;
        RECT 201.530 214.430 201.670 214.765 ;
        RECT 202.490 214.430 202.630 214.765 ;
        RECT 203.450 214.430 203.590 214.765 ;
        RECT 204.410 214.430 204.550 214.765 ;
        RECT 205.370 214.430 205.510 214.765 ;
        RECT 206.330 214.430 206.470 214.765 ;
        RECT 207.290 214.430 214.665 214.765 ;
        RECT 0.375 0.610 214.665 214.430 ;
        RECT 0.375 0.275 1.990 0.610 ;
        RECT 2.810 0.275 2.950 0.610 ;
        RECT 3.770 0.275 3.910 0.610 ;
        RECT 4.730 0.275 4.870 0.610 ;
        RECT 5.690 0.275 10.630 0.610 ;
        RECT 11.450 0.275 11.590 0.610 ;
        RECT 12.410 0.275 12.550 0.610 ;
        RECT 13.370 0.275 13.510 0.610 ;
        RECT 14.330 0.275 14.470 0.610 ;
        RECT 15.290 0.275 15.430 0.610 ;
        RECT 16.250 0.275 16.390 0.610 ;
        RECT 17.210 0.275 17.350 0.610 ;
        RECT 18.170 0.275 24.070 0.610 ;
        RECT 24.890 0.275 25.030 0.610 ;
        RECT 25.850 0.275 25.990 0.610 ;
        RECT 26.810 0.275 26.950 0.610 ;
        RECT 27.770 0.275 27.910 0.610 ;
        RECT 28.730 0.275 28.870 0.610 ;
        RECT 29.690 0.275 29.830 0.610 ;
        RECT 30.650 0.275 30.790 0.610 ;
        RECT 31.610 0.275 40.390 0.610 ;
        RECT 41.210 0.275 41.350 0.610 ;
        RECT 42.170 0.275 42.310 0.610 ;
        RECT 43.130 0.275 43.270 0.610 ;
        RECT 44.090 0.275 44.230 0.610 ;
        RECT 45.050 0.275 45.190 0.610 ;
        RECT 46.010 0.275 46.150 0.610 ;
        RECT 46.970 0.275 47.110 0.610 ;
        RECT 47.930 0.275 48.070 0.610 ;
        RECT 48.890 0.275 49.030 0.610 ;
        RECT 49.850 0.275 49.990 0.610 ;
        RECT 50.810 0.275 50.950 0.610 ;
        RECT 51.770 0.275 51.910 0.610 ;
        RECT 52.730 0.275 52.870 0.610 ;
        RECT 53.690 0.275 53.830 0.610 ;
        RECT 54.650 0.275 54.790 0.610 ;
        RECT 55.610 0.275 68.230 0.610 ;
        RECT 69.050 0.275 69.190 0.610 ;
        RECT 70.010 0.275 70.150 0.610 ;
        RECT 70.970 0.275 71.110 0.610 ;
        RECT 71.930 0.275 72.070 0.610 ;
        RECT 72.890 0.275 73.030 0.610 ;
        RECT 73.850 0.275 73.990 0.610 ;
        RECT 74.810 0.275 74.950 0.610 ;
        RECT 75.770 0.275 75.910 0.610 ;
        RECT 76.730 0.275 76.870 0.610 ;
        RECT 77.690 0.275 77.830 0.610 ;
        RECT 78.650 0.275 78.790 0.610 ;
        RECT 79.610 0.275 79.750 0.610 ;
        RECT 80.570 0.275 80.710 0.610 ;
        RECT 81.530 0.275 81.670 0.610 ;
        RECT 82.490 0.275 82.630 0.610 ;
        RECT 83.450 0.275 90.310 0.610 ;
        RECT 91.130 0.275 91.270 0.610 ;
        RECT 92.090 0.275 92.230 0.610 ;
        RECT 93.050 0.275 93.190 0.610 ;
        RECT 94.010 0.275 98.950 0.610 ;
        RECT 99.770 0.275 99.910 0.610 ;
        RECT 100.730 0.275 100.870 0.610 ;
        RECT 101.690 0.275 101.830 0.610 ;
        RECT 102.650 0.275 102.790 0.610 ;
        RECT 103.610 0.275 103.750 0.610 ;
        RECT 104.570 0.275 104.710 0.610 ;
        RECT 105.530 0.275 105.670 0.610 ;
        RECT 106.490 0.275 112.390 0.610 ;
        RECT 113.210 0.275 113.350 0.610 ;
        RECT 114.170 0.275 114.310 0.610 ;
        RECT 115.130 0.275 115.270 0.610 ;
        RECT 116.090 0.275 116.230 0.610 ;
        RECT 117.050 0.275 117.190 0.610 ;
        RECT 118.010 0.275 118.150 0.610 ;
        RECT 118.970 0.275 119.110 0.610 ;
        RECT 119.930 0.275 128.710 0.610 ;
        RECT 129.530 0.275 129.670 0.610 ;
        RECT 130.490 0.275 130.630 0.610 ;
        RECT 131.450 0.275 131.590 0.610 ;
        RECT 132.410 0.275 132.550 0.610 ;
        RECT 133.370 0.275 133.510 0.610 ;
        RECT 134.330 0.275 134.470 0.610 ;
        RECT 135.290 0.275 135.430 0.610 ;
        RECT 136.250 0.275 136.390 0.610 ;
        RECT 137.210 0.275 137.350 0.610 ;
        RECT 138.170 0.275 138.310 0.610 ;
        RECT 139.130 0.275 139.270 0.610 ;
        RECT 140.090 0.275 140.230 0.610 ;
        RECT 141.050 0.275 141.190 0.610 ;
        RECT 142.010 0.275 142.150 0.610 ;
        RECT 142.970 0.275 143.110 0.610 ;
        RECT 143.930 0.275 156.550 0.610 ;
        RECT 157.370 0.275 157.510 0.610 ;
        RECT 158.330 0.275 158.470 0.610 ;
        RECT 159.290 0.275 159.430 0.610 ;
        RECT 160.250 0.275 160.390 0.610 ;
        RECT 161.210 0.275 161.350 0.610 ;
        RECT 162.170 0.275 162.310 0.610 ;
        RECT 163.130 0.275 163.270 0.610 ;
        RECT 164.090 0.275 164.230 0.610 ;
        RECT 165.050 0.275 165.190 0.610 ;
        RECT 166.010 0.275 166.150 0.610 ;
        RECT 166.970 0.275 167.110 0.610 ;
        RECT 167.930 0.275 168.070 0.610 ;
        RECT 168.890 0.275 169.030 0.610 ;
        RECT 169.850 0.275 169.990 0.610 ;
        RECT 170.810 0.275 170.950 0.610 ;
        RECT 171.770 0.275 178.630 0.610 ;
        RECT 179.450 0.275 188.230 0.610 ;
        RECT 189.050 0.275 189.190 0.610 ;
        RECT 190.010 0.275 190.150 0.610 ;
        RECT 190.970 0.275 191.110 0.610 ;
        RECT 191.930 0.275 192.070 0.610 ;
        RECT 192.890 0.275 193.030 0.610 ;
        RECT 193.850 0.275 193.990 0.610 ;
        RECT 194.810 0.275 194.950 0.610 ;
        RECT 195.770 0.275 195.910 0.610 ;
        RECT 196.730 0.275 196.870 0.610 ;
        RECT 197.690 0.275 197.830 0.610 ;
        RECT 198.650 0.275 198.790 0.610 ;
        RECT 199.610 0.275 199.750 0.610 ;
        RECT 200.570 0.275 200.710 0.610 ;
        RECT 201.530 0.275 201.670 0.610 ;
        RECT 202.490 0.275 202.630 0.610 ;
        RECT 203.450 0.275 203.590 0.610 ;
        RECT 204.410 0.275 204.550 0.610 ;
        RECT 205.370 0.275 205.510 0.610 ;
        RECT 206.330 0.275 206.470 0.610 ;
        RECT 207.290 0.275 214.665 0.610 ;
      LAYER Metal3 ;
        RECT 0.335 201.590 214.705 214.725 ;
        RECT 0.610 200.770 214.430 201.590 ;
        RECT 0.335 200.750 214.705 200.770 ;
        RECT 0.610 199.930 214.430 200.750 ;
        RECT 0.335 199.910 214.705 199.930 ;
        RECT 0.610 199.090 214.430 199.910 ;
        RECT 0.335 199.070 214.705 199.090 ;
        RECT 0.610 198.250 214.430 199.070 ;
        RECT 0.335 198.230 214.705 198.250 ;
        RECT 0.610 197.410 214.430 198.230 ;
        RECT 0.335 197.390 214.705 197.410 ;
        RECT 0.610 196.570 214.430 197.390 ;
        RECT 0.335 196.550 214.705 196.570 ;
        RECT 0.610 195.730 214.430 196.550 ;
        RECT 0.335 195.710 214.705 195.730 ;
        RECT 0.610 194.890 214.430 195.710 ;
        RECT 0.335 194.870 214.705 194.890 ;
        RECT 0.610 194.050 214.430 194.870 ;
        RECT 0.335 194.030 214.705 194.050 ;
        RECT 0.610 193.210 214.430 194.030 ;
        RECT 0.335 193.190 214.705 193.210 ;
        RECT 0.610 192.370 214.430 193.190 ;
        RECT 0.335 192.350 214.705 192.370 ;
        RECT 0.610 191.530 214.430 192.350 ;
        RECT 0.335 191.510 214.705 191.530 ;
        RECT 0.610 190.690 214.430 191.510 ;
        RECT 0.335 190.670 214.705 190.690 ;
        RECT 0.610 189.850 214.430 190.670 ;
        RECT 0.335 189.830 214.705 189.850 ;
        RECT 0.610 189.010 214.430 189.830 ;
        RECT 0.335 188.990 214.705 189.010 ;
        RECT 0.610 188.170 214.430 188.990 ;
        RECT 0.335 188.150 214.705 188.170 ;
        RECT 0.610 187.330 214.430 188.150 ;
        RECT 0.335 187.310 214.705 187.330 ;
        RECT 0.610 186.490 214.430 187.310 ;
        RECT 0.335 186.470 214.705 186.490 ;
        RECT 0.610 185.650 214.430 186.470 ;
        RECT 0.335 185.630 214.705 185.650 ;
        RECT 0.610 184.810 214.430 185.630 ;
        RECT 0.335 184.790 214.705 184.810 ;
        RECT 0.610 183.970 214.430 184.790 ;
        RECT 0.335 183.950 214.705 183.970 ;
        RECT 0.610 183.130 214.430 183.950 ;
        RECT 0.335 183.110 214.705 183.130 ;
        RECT 0.610 182.290 214.430 183.110 ;
        RECT 0.335 182.270 214.705 182.290 ;
        RECT 0.610 181.450 214.430 182.270 ;
        RECT 0.335 181.430 214.705 181.450 ;
        RECT 0.610 180.610 214.430 181.430 ;
        RECT 0.335 180.590 214.705 180.610 ;
        RECT 0.610 179.770 214.430 180.590 ;
        RECT 0.335 179.750 214.705 179.770 ;
        RECT 0.610 178.930 214.430 179.750 ;
        RECT 0.335 178.910 214.705 178.930 ;
        RECT 0.610 178.090 214.430 178.910 ;
        RECT 0.335 178.070 214.705 178.090 ;
        RECT 0.610 177.250 214.430 178.070 ;
        RECT 0.335 177.230 214.705 177.250 ;
        RECT 0.610 176.410 214.430 177.230 ;
        RECT 0.335 176.390 214.705 176.410 ;
        RECT 0.610 175.570 214.430 176.390 ;
        RECT 0.335 175.550 214.705 175.570 ;
        RECT 0.610 174.730 214.430 175.550 ;
        RECT 0.335 161.270 214.705 174.730 ;
        RECT 0.610 160.450 214.430 161.270 ;
        RECT 0.335 159.590 214.705 160.450 ;
        RECT 0.610 158.770 214.430 159.590 ;
        RECT 0.335 157.910 214.705 158.770 ;
        RECT 0.610 157.090 214.430 157.910 ;
        RECT 0.335 156.230 214.705 157.090 ;
        RECT 0.610 155.410 214.430 156.230 ;
        RECT 0.335 154.550 214.705 155.410 ;
        RECT 0.610 153.730 214.430 154.550 ;
        RECT 0.335 152.870 214.705 153.730 ;
        RECT 0.610 152.050 214.430 152.870 ;
        RECT 0.335 151.190 214.705 152.050 ;
        RECT 0.610 150.370 214.430 151.190 ;
        RECT 0.335 149.510 214.705 150.370 ;
        RECT 0.610 148.690 214.430 149.510 ;
        RECT 0.335 147.830 214.705 148.690 ;
        RECT 0.610 147.010 214.430 147.830 ;
        RECT 0.335 146.150 214.705 147.010 ;
        RECT 0.610 145.330 214.430 146.150 ;
        RECT 0.335 144.470 214.705 145.330 ;
        RECT 0.610 143.650 214.430 144.470 ;
        RECT 0.335 142.790 214.705 143.650 ;
        RECT 0.610 141.970 214.430 142.790 ;
        RECT 0.335 141.110 214.705 141.970 ;
        RECT 0.610 140.290 214.430 141.110 ;
        RECT 0.335 139.430 214.705 140.290 ;
        RECT 0.610 138.610 214.430 139.430 ;
        RECT 0.335 137.750 214.705 138.610 ;
        RECT 0.610 136.930 214.430 137.750 ;
        RECT 0.335 136.070 214.705 136.930 ;
        RECT 0.610 135.250 214.430 136.070 ;
        RECT 0.335 134.390 214.705 135.250 ;
        RECT 0.610 133.570 214.430 134.390 ;
        RECT 0.335 132.710 214.705 133.570 ;
        RECT 0.610 131.890 214.430 132.710 ;
        RECT 0.335 131.030 214.705 131.890 ;
        RECT 0.610 130.210 214.430 131.030 ;
        RECT 0.335 129.350 214.705 130.210 ;
        RECT 0.610 128.530 214.430 129.350 ;
        RECT 0.335 127.670 214.705 128.530 ;
        RECT 0.610 126.850 214.430 127.670 ;
        RECT 0.335 125.990 214.705 126.850 ;
        RECT 0.610 125.170 214.430 125.990 ;
        RECT 0.335 124.310 214.705 125.170 ;
        RECT 0.610 123.490 214.430 124.310 ;
        RECT 0.335 122.630 214.705 123.490 ;
        RECT 0.610 121.810 214.430 122.630 ;
        RECT 0.335 120.950 214.705 121.810 ;
        RECT 0.610 120.130 214.430 120.950 ;
        RECT 0.335 119.270 214.705 120.130 ;
        RECT 0.610 118.450 214.430 119.270 ;
        RECT 0.335 117.590 214.705 118.450 ;
        RECT 0.610 116.770 214.430 117.590 ;
        RECT 0.335 115.910 214.705 116.770 ;
        RECT 0.610 115.090 214.430 115.910 ;
        RECT 0.335 114.230 214.705 115.090 ;
        RECT 0.610 113.410 214.430 114.230 ;
        RECT 0.335 112.550 214.705 113.410 ;
        RECT 0.610 111.730 214.430 112.550 ;
        RECT 0.335 110.870 214.705 111.730 ;
        RECT 0.610 110.050 214.430 110.870 ;
        RECT 0.335 109.190 214.705 110.050 ;
        RECT 0.610 108.370 214.430 109.190 ;
        RECT 0.335 107.510 214.705 108.370 ;
        RECT 0.610 106.690 214.430 107.510 ;
        RECT 0.335 105.830 214.705 106.690 ;
        RECT 0.610 105.010 214.430 105.830 ;
        RECT 0.335 104.150 214.705 105.010 ;
        RECT 0.610 103.330 214.430 104.150 ;
        RECT 0.335 102.470 214.705 103.330 ;
        RECT 0.610 101.650 214.430 102.470 ;
        RECT 0.335 100.790 214.705 101.650 ;
        RECT 0.610 99.970 214.430 100.790 ;
        RECT 0.335 99.110 214.705 99.970 ;
        RECT 0.610 98.290 214.430 99.110 ;
        RECT 0.335 97.430 214.705 98.290 ;
        RECT 0.610 96.610 214.430 97.430 ;
        RECT 0.335 95.750 214.705 96.610 ;
        RECT 0.610 94.930 214.430 95.750 ;
        RECT 0.335 94.070 214.705 94.930 ;
        RECT 0.610 93.250 214.430 94.070 ;
        RECT 0.335 92.390 214.705 93.250 ;
        RECT 0.610 91.570 214.430 92.390 ;
        RECT 0.335 90.710 214.705 91.570 ;
        RECT 0.610 89.890 214.430 90.710 ;
        RECT 0.335 89.030 214.705 89.890 ;
        RECT 0.610 88.210 214.430 89.030 ;
        RECT 0.335 87.350 214.705 88.210 ;
        RECT 0.610 86.530 214.430 87.350 ;
        RECT 0.335 85.670 214.705 86.530 ;
        RECT 0.610 84.850 214.430 85.670 ;
        RECT 0.335 83.990 214.705 84.850 ;
        RECT 0.610 83.170 214.430 83.990 ;
        RECT 0.335 82.310 214.705 83.170 ;
        RECT 0.610 81.490 214.430 82.310 ;
        RECT 0.335 80.630 214.705 81.490 ;
        RECT 0.610 79.810 214.430 80.630 ;
        RECT 0.335 78.950 214.705 79.810 ;
        RECT 0.610 78.130 214.430 78.950 ;
        RECT 0.335 77.270 214.705 78.130 ;
        RECT 0.610 76.450 214.430 77.270 ;
        RECT 0.335 75.590 214.705 76.450 ;
        RECT 0.610 74.770 214.430 75.590 ;
        RECT 0.335 73.910 214.705 74.770 ;
        RECT 0.610 73.090 214.430 73.910 ;
        RECT 0.335 72.230 214.705 73.090 ;
        RECT 0.610 71.410 214.430 72.230 ;
        RECT 0.335 70.550 214.705 71.410 ;
        RECT 0.610 69.730 214.430 70.550 ;
        RECT 0.335 68.870 214.705 69.730 ;
        RECT 0.610 68.050 214.430 68.870 ;
        RECT 0.335 67.190 214.705 68.050 ;
        RECT 0.610 66.370 214.430 67.190 ;
        RECT 0.335 65.510 214.705 66.370 ;
        RECT 0.610 64.690 214.430 65.510 ;
        RECT 0.335 63.830 214.705 64.690 ;
        RECT 0.610 63.010 214.430 63.830 ;
        RECT 0.335 62.150 214.705 63.010 ;
        RECT 0.610 61.330 214.430 62.150 ;
        RECT 0.335 60.470 214.705 61.330 ;
        RECT 0.610 59.650 214.430 60.470 ;
        RECT 0.335 52.910 214.705 59.650 ;
        RECT 0.610 52.090 214.430 52.910 ;
        RECT 0.335 52.070 214.705 52.090 ;
        RECT 0.610 51.250 214.430 52.070 ;
        RECT 0.335 51.230 214.705 51.250 ;
        RECT 0.610 50.410 214.430 51.230 ;
        RECT 0.335 50.390 214.705 50.410 ;
        RECT 0.610 49.570 214.430 50.390 ;
        RECT 0.335 49.550 214.705 49.570 ;
        RECT 0.610 48.730 214.430 49.550 ;
        RECT 0.335 48.710 214.705 48.730 ;
        RECT 0.610 47.890 214.430 48.710 ;
        RECT 0.335 47.870 214.705 47.890 ;
        RECT 0.610 47.050 214.430 47.870 ;
        RECT 0.335 47.030 214.705 47.050 ;
        RECT 0.610 46.210 214.430 47.030 ;
        RECT 0.335 46.190 214.705 46.210 ;
        RECT 0.610 45.370 214.430 46.190 ;
        RECT 0.335 45.350 214.705 45.370 ;
        RECT 0.610 44.530 214.430 45.350 ;
        RECT 0.335 44.510 214.705 44.530 ;
        RECT 0.610 43.690 214.430 44.510 ;
        RECT 0.335 43.670 214.705 43.690 ;
        RECT 0.610 42.850 214.430 43.670 ;
        RECT 0.335 42.830 214.705 42.850 ;
        RECT 0.610 42.010 214.430 42.830 ;
        RECT 0.335 41.990 214.705 42.010 ;
        RECT 0.610 41.170 214.430 41.990 ;
        RECT 0.335 41.150 214.705 41.170 ;
        RECT 0.610 40.330 214.430 41.150 ;
        RECT 0.335 40.310 214.705 40.330 ;
        RECT 0.610 39.490 214.430 40.310 ;
        RECT 0.335 32.750 214.705 39.490 ;
        RECT 0.610 31.930 214.430 32.750 ;
        RECT 0.335 31.070 214.705 31.930 ;
        RECT 0.610 30.250 214.430 31.070 ;
        RECT 0.335 29.390 214.705 30.250 ;
        RECT 0.610 28.570 214.430 29.390 ;
        RECT 0.335 27.710 214.705 28.570 ;
        RECT 0.610 26.890 214.430 27.710 ;
        RECT 0.335 26.030 214.705 26.890 ;
        RECT 0.610 25.210 214.430 26.030 ;
        RECT 0.335 24.350 214.705 25.210 ;
        RECT 0.610 23.530 214.430 24.350 ;
        RECT 0.335 22.670 214.705 23.530 ;
        RECT 0.610 21.850 214.430 22.670 ;
        RECT 0.335 20.990 214.705 21.850 ;
        RECT 0.610 20.170 214.430 20.990 ;
        RECT 0.335 16.790 214.705 20.170 ;
        RECT 0.610 15.970 214.430 16.790 ;
        RECT 0.335 15.950 214.705 15.970 ;
        RECT 0.610 15.130 214.430 15.950 ;
        RECT 0.335 15.110 214.705 15.130 ;
        RECT 0.610 14.290 214.430 15.110 ;
        RECT 0.335 14.270 214.705 14.290 ;
        RECT 0.610 13.450 214.430 14.270 ;
        RECT 0.335 13.430 214.705 13.450 ;
        RECT 0.610 12.610 214.430 13.430 ;
        RECT 0.335 12.590 214.705 12.610 ;
        RECT 0.610 11.770 214.430 12.590 ;
        RECT 0.335 11.750 214.705 11.770 ;
        RECT 0.610 10.930 214.430 11.750 ;
        RECT 0.335 10.910 214.705 10.930 ;
        RECT 0.610 10.090 214.430 10.910 ;
        RECT 0.335 6.710 214.705 10.090 ;
        RECT 0.610 5.890 214.430 6.710 ;
        RECT 0.335 5.030 214.705 5.890 ;
        RECT 0.610 4.210 214.430 5.030 ;
        RECT 0.335 3.350 214.705 4.210 ;
        RECT 0.610 2.530 214.430 3.350 ;
        RECT 0.335 1.670 214.705 2.530 ;
        RECT 0.610 0.850 214.430 1.670 ;
        RECT 0.335 0.315 214.705 0.850 ;
      LAYER Metal4 ;
        RECT 0.380 0.275 15.170 214.765 ;
        RECT 17.790 0.275 21.370 214.765 ;
        RECT 23.990 0.275 90.770 214.765 ;
        RECT 93.390 0.275 96.970 214.765 ;
        RECT 99.590 0.275 166.370 214.765 ;
        RECT 168.990 0.275 172.570 214.765 ;
        RECT 175.190 0.275 214.660 214.765 ;
      LAYER TopMetal1 ;
        RECT 2.540 3.100 212.500 198.540 ;
  END
END LUT4AB
END LIBRARY

